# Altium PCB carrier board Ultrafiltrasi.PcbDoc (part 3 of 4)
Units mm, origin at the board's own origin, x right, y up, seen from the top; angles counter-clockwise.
Board outline 216.53 x 247.52 mm, 2 copper layers (Top Layer, Bottom Layer); 114 components, 209 nets, 667 pads, 68 vias.
Unrouted connection lines stored in the file: 3.

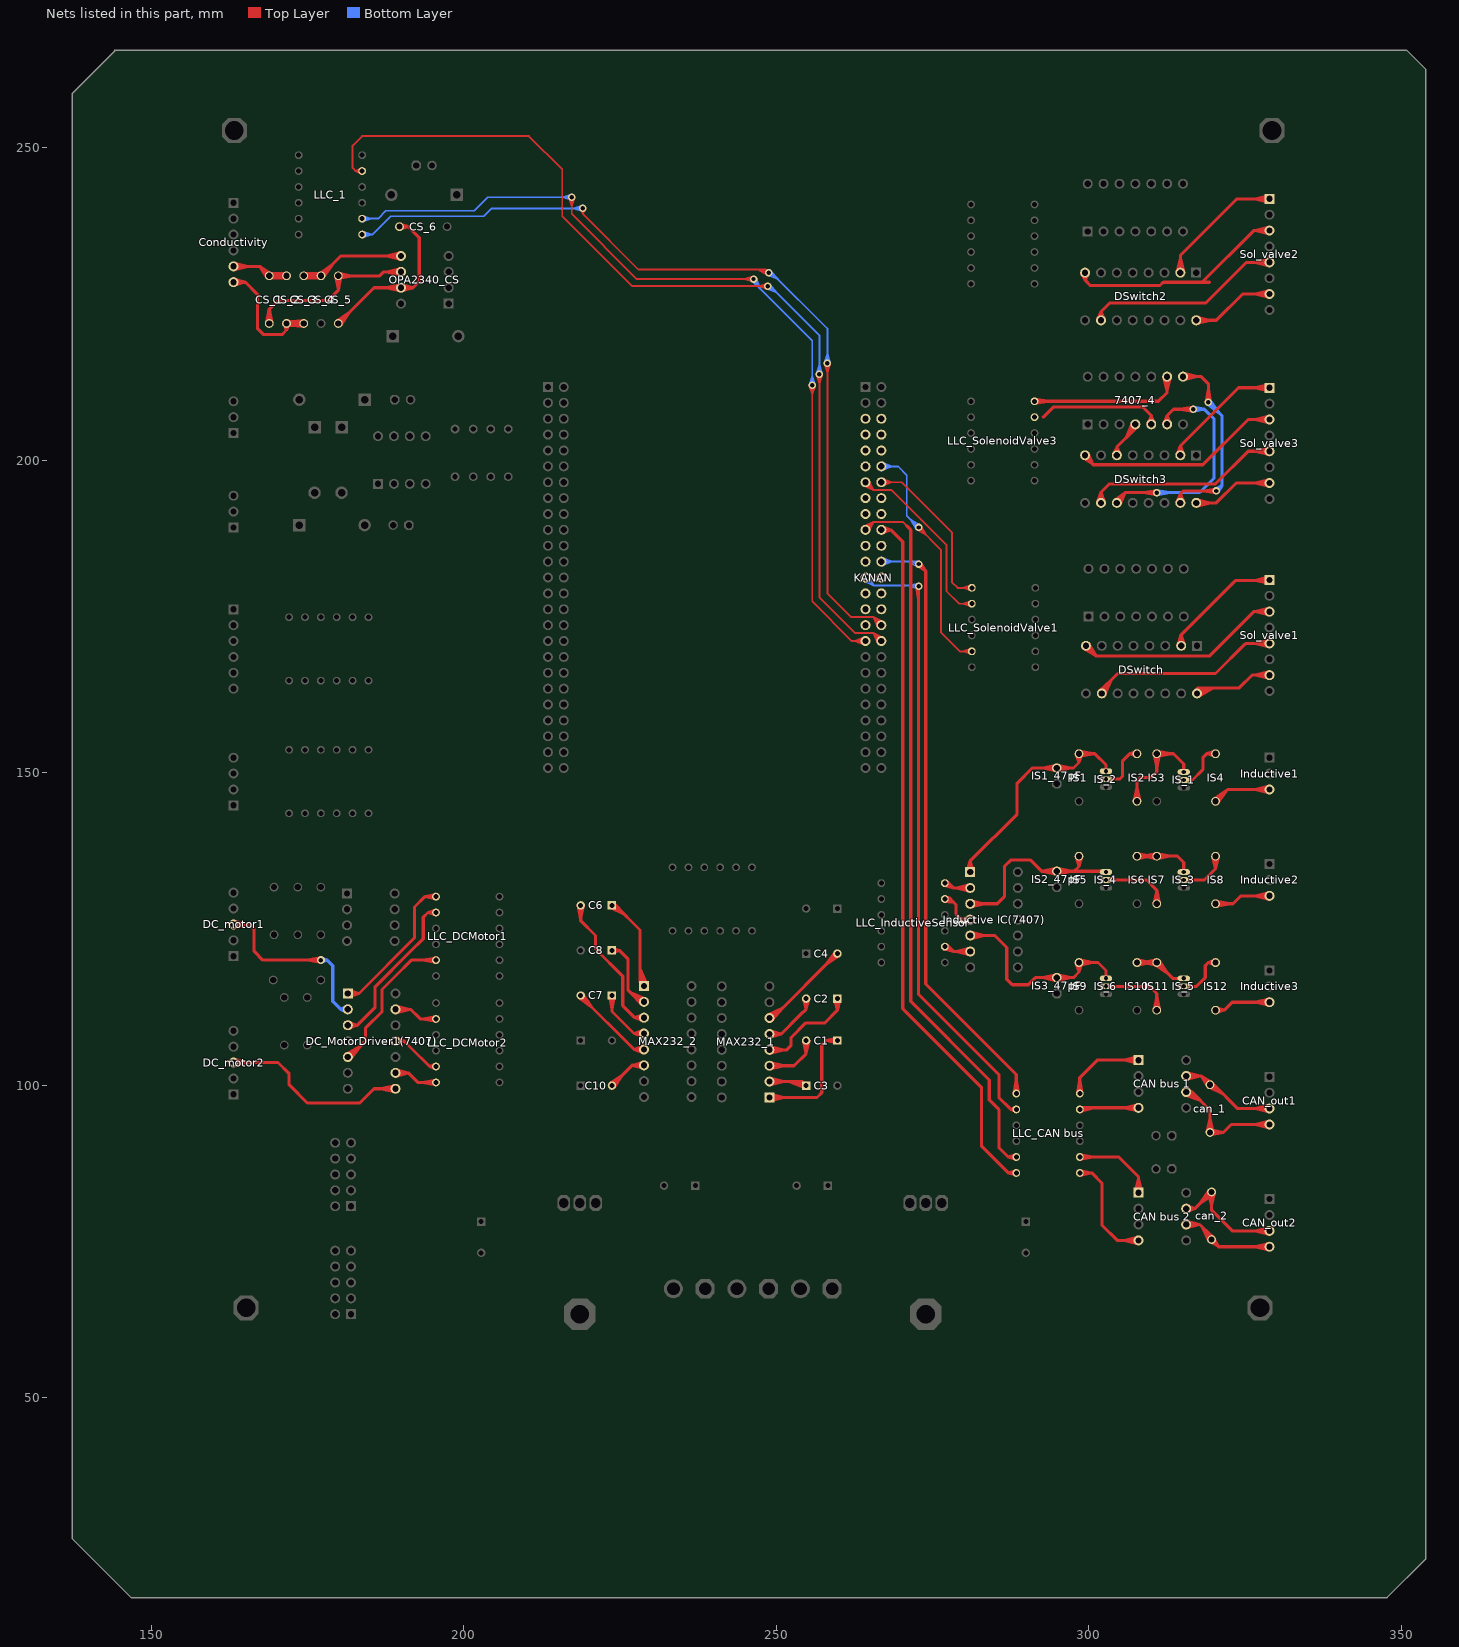
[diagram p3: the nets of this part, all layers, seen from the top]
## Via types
v1: diameter 1.2, hole 0.711, Top Layer to Bottom Layer, 27 vias
v2: diameter 1.27, hole 0.711, Top Layer to Bottom Layer, 21 vias
v3: diameter 1.2, hole 0.7, Top Layer to Bottom Layer, 19 vias
v4: diameter 1.5, hole 0.8, Top Layer to Bottom Layer, 1 vias

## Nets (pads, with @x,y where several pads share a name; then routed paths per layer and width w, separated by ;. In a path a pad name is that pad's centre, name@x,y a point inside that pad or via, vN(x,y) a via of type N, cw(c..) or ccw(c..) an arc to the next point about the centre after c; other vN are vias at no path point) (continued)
Net7407_4_4: 7407_4.4 DSwitch3.6 | length 16.9
  Top Layer w0.5: DSwitch3.6@303.969,200.903 304.507,202.096 ; DSwitch3.6@304.507,200.787 304.507,202.096 ; DSwitch3.6@305.045,200.903 304.507,202.096 ; 7407_4.4@306.985,206.005 305.94,203.529 ; 7407_4.4@307.885,205.383 305.94,203.529 ; 304.507,202.096 307.467,205.056 7407_4.4@307.467,205.74 305.94,203.529
Net7407_4_5: 7407_4.5 LLC_SolenoidValve3.P$11 | length 23.1
  Top Layer w0.5: LLC_SolenoidValve3.P$11@291.338,206.883 LLC_SolenoidValve3.P$11@291.611,207.156 ; 292.735,206.883 294.386,208.534 308.61,208.534 310.007,207.137 ; 7407_4.5@309.468,205.848 310.007,207.137 ; 7407_4.5@310.007,205.74 310.007,207.137 ; 7407_4.5@310.546,205.848 310.007,207.137
Net7407_4_6: 7407_4.6 DSwitch3.11 | length 64.6
  Top Layer w0.5: DSwitch3.11@304.124,193.562 305.816,194.818 ; DSwitch3.11@304.979,192.884 305.816,194.818 ; v3@310.867,194.469 308.796,194.818 v3@310.867,195.167 ; v3@311.162,195.072 311.15,195.072 v3(310.896,194.818) 305.816,194.818 ; 7407_4.6@312.008,205.848 312.547,207.137 ; 7407_4.6@312.547,205.74 312.547,207.137 ; 7407_4.6@313.086,205.848 312.547,207.137 ; v1@316.709,207.804 314.638,208.153 ; v1@316.709,208.502 314.638,208.153 ; 305.816,194.818 DSwitch3.11@304.507,193.167 304.507,193.509 305.816,194.818 ; 312.547,207.137 313.563,208.153 v1(316.738,208.153) 314.638,208.153
  Bottom Layer w0.5: v3(310.896,194.818) 317.754,194.818 320.04,197.104 320.04,206.629 318.516,208.153 ; v3@310.925,194.469 312.996,194.818 v3@310.925,195.167 ; v1(316.738,208.153) 318.516,208.153 ; v1@316.772,207.805 318.516,208.153 ; v1@316.772,208.501 318.516,208.153
Net7407_4_8: 7407_4.8 DSwitch3.15 | length 55.5
  Top Layer w0.5: DSwitch3.15@314.127,193.272 314.667,194.603 ; DSwitch3.15@314.667,193.167 314.667,194.603 ; 7407_4.8@315.087,213.36 318.008,213.36 319.151,212.217 v3(319.151,209.296) ; 7407_4.8@315.153,212.814 317.387,213.36 7407_4.8@315.153,213.906 ; DSwitch3.15@315.207,193.272 314.667,194.603 ; v3@318.802,209.325 319.151,211.396 v3@319.5,209.325 ; v3@320.392,194.723 318.321,195.072 ; v3@320.392,195.421 318.321,195.072 ; 314.667,194.603 315.136,195.072 v3(320.421,195.072) 318.321,195.072
  Bottom Layer w0.5: v3@318.923,209.031 320.812,207.635 v3@319.416,209.524 ; v3(319.151,209.296) 321.31,207.137 321.31,195.961 ; v3@320.21,195.352 321.31,195.961 ; v3(320.421,195.072) 321.31,195.961 ; v3@320.701,194.861 321.31,195.961
Net7407_4_9: 7407_4.9 LLC_SolenoidValve3.P$12 | length 33.2
  Top Layer w0.5: LLC_SolenoidValve3.P$12@291.338,209.423 311.15,209.423 312.547,210.82 7407_4.9@312.547,213.36 ; LLC_SolenoidValve3.P$12@291.371,209.049 293.463,209.423 LLC_SolenoidValve3.P$12@291.371,209.797 ; 7407_4.9@312.001,213.294 312.547,211.06 7407_4.9@313.093,213.294
NetC1_1: C1.1 MAX232_1.1 | length 27.3
  Top Layer w0.5: MAX232_1.1@248.92,98.044 256.54,98.044 257.302,98.806 257.302,106.426 258.032,107.156 ; MAX232_1.1@248.986,97.498 251.22,98.044 MAX232_1.1@248.986,98.59 ; C1.1@259.751,106.734 258.032,107.156 ; C1.1@259.751,107.578 258.032,107.156 ; C1.1@259.802,107.156 258.032,107.156
NetC1_2: C1.2 MAX232_1.3 | length 19.6
  Top Layer w0.5: MAX232_1.3@248.92,103.124 252.857,103.124 254.802,105.069 ; MAX232_1.3@248.986,102.578 251.22,103.124 MAX232_1.3@248.986,103.67 ; C1.2@254.379,107.113 254.802,105.069 ; C1.2@255.225,107.113 254.802,105.069 ; 254.802,105.069 C1.2@254.802,107.156 254.802,105.069
NetC2_1: C2.1 MAX232_1.4 | length 26.6
  Top Layer w0.5: MAX232_1.4@248.92,105.664 251.714,105.664 252.349,106.299 252.349,107.569 254.762,109.982 257.81,109.982 259.802,111.974 ; MAX232_1.4@248.986,105.118 251.22,105.664 MAX232_1.4@248.986,106.21 ; C2.1@259.38,113.807 259.802,111.974 ; C2.1@259.802,113.855 259.802,111.974 ; C2.1@259.802,114.088 259.802,111.974 ; C2.1@260.224,113.807 259.802,111.974
NetC2_2: C2.2 MAX232_1.5 | length 18
  Top Layer w0.5: MAX232_1.5@248.92,108.204 250.825,108.204 ; MAX232_1.5@248.999,107.66 250.825,108.204 ; MAX232_1.5@248.999,108.748 250.825,108.204 ; C2.2@254.38,113.802 254.802,112.181 ; C2.2@255.224,113.802 254.802,112.181 ; 250.825,108.204 253.873,111.252 254.802,112.181 ; 254.802,112.181 C2.2@254.802,113.855 254.802,112.181
NetC3_1: C3.1 MAX232_1.2 | length 19.1
  Top Layer w0.5: MAX232_1.2@248.92,100.584 254.167,100.584 C3.1@254.802,99.949 252.103,100.584 ; MAX232_1.2@248.986,100.038 251.22,100.584 MAX232_1.2@248.986,101.13 ; C3.1@254.673,99.544 252.103,100.584 ; C3.1@254.867,100.369 252.103,100.584
NetC4_2: C4.2 MAX232_1.6 | length 30.6
  Top Layer w0.5: MAX232_1.6@248.633,111.213 251.066,112.382 ; MAX232_1.6@249.297,110.343 251.066,112.382 ; C4.2@259.481,121.341 258.04,119.356 ; C4.2@259.774,121.09 249.428,110.744 MAX232_1.6@248.92,110.744 251.066,112.382 ; C4.2@259.802,121.063 258.04,119.356 ; C4.2@260.07,120.733 258.04,119.356
NetC6_1: C6.1 MAX232_2.1 | length 31.3
  Top Layer w0.5: C6.1@223.513,128.415 225.771,127.289 ; C6.1@224.013,129.099 225.771,127.289 ; MAX232_2.1@228.309,115.821 228.219,118.628 ; MAX232_2.1@229.375,116.068 228.219,118.628 ; 225.771,127.289 C6.1@223.734,128.778 224.282,128.778 228.219,124.841 228.219,116.527 MAX232_2.1@228.854,115.892 228.219,118.628
NetC6_2: C6.2 MAX232_2.3 | length 31.8
  Top Layer w0.5: C6.2@218.311,128.736 218.734,126.603 C6.2@219.157,128.736 ; C6.2@218.734,128.778 218.734,126.325 221.107,123.952 221.107,121.793 225.464,117.436 225.464,112.737 227.389,110.812 ; MAX232_2.3@228.751,110.272 227.389,110.812 ; MAX232_2.3@228.751,111.352 227.389,110.812 ; 227.389,110.812 MAX232_2.3@228.854,110.812 227.389,110.812
NetC7_1: C7.1 MAX232_2.4 | length 20.4
  Top Layer w0.5: C7.1@223.311,114.322 223.734,112.189 ; C7.1@224.157,114.322 223.734,112.189 ; MAX232_2.4@228.759,107.73 227.262,108.272 ; MAX232_2.4@228.759,108.814 227.262,108.272 ; 223.734,112.189 C7.1@223.734,114.364 223.734,111.8 227.262,108.272 ; 227.262,108.272 MAX232_2.4@228.854,108.272 227.262,108.272
NetC7_2: C7.2 MAX232_2.5 | length 24.3
  Top Layer w0.5: C7.2@218.451,114.046 220.415,112.579 ; C7.2@218.63,114.364 227.262,105.732 ; C7.2@218.734,114.364 220.415,112.579 ; C7.2@219.067,114.627 220.415,112.579 ; MAX232_2.5@228.759,105.19 227.262,105.732 ; MAX232_2.5@228.759,106.274 227.262,105.732 ; MAX232_2.5@228.854,105.732 227.262,105.732
NetC8_1: C8.1 MAX232_2.2 | length 21.6
  Top Layer w0.5: C8.1@223.734,121.571 224.885,121.571 ; C8.1@223.812,121.153 224.885,121.571 ; C8.1@223.812,121.988 224.885,121.571 ; MAX232_2.2@228.5,112.931 226.676,114.827 ; MAX232_2.2@229.113,113.837 226.676,114.827 ; 224.885,121.571 226.314,120.142 226.314,115.189 228.151,113.352 MAX232_2.2@228.854,113.352 226.676,114.827
NetC10_2: C10.2 MAX232_2.6 | length 15.1
  Top Layer w0.5: C10.2@223.461,100.274 225.47,101.685 C10.2@224.059,99.676 ; C10.2@223.734,99.949 226.977,103.192 ; MAX232_2.6@228.773,102.648 226.977,103.192 ; MAX232_2.6@228.773,103.736 226.977,103.192 ; MAX232_2.6@228.854,103.192 226.977,103.192
"NetCAN bus 1_1": "CAN bus 1.1" "LLC_CAN bus.P$12" | length 21.9
  Top Layer w0.5: 298.203,98.712 298.577,100.804 298.951,98.712 ; 298.577,98.679 298.577,101.219 301.371,104.013 307.975,104.013 ; 307.909,103.467 305.675,104.013 307.909,104.559
"NetCAN bus 1_4": "CAN bus 1.4" "LLC_CAN bus.P$11" | length 23
  Top Layer w0.5: 298.566,96.514 300.771,96.393 ; 298.652,95.771 300.771,96.393 ; 307.909,95.847 305.675,96.393 ; 307.909,96.939 305.675,96.393 ; 300.771,96.393 298.577,96.139 298.831,96.393 307.975,96.393 305.675,96.393
"NetCAN bus 2_1": "CAN bus 2.1" "LLC_CAN bus.P$8" | length 22.1
  Top Layer w0.5: 298.577,88.519 304.8,88.519 307.975,85.344 307.975,82.804 ; 298.61,88.145 300.702,88.519 298.61,88.893 ; 307.429,82.87 307.975,85.104 308.521,82.87
"NetCAN bus 2_4": "CAN bus 2.4" "LLC_CAN bus.P$7" | length 26.2
  Top Layer w0.5: 298.577,85.979 300.482,85.979 ; 298.614,85.606 300.482,85.979 ; 298.614,86.352 300.482,85.979 ; 307.909,74.638 305.675,75.184 307.909,75.73 ; 307.975,75.184 304.546,75.184 302.133,77.597 302.133,84.328 300.482,85.979
Netcan_1_1: "CAN bus 1.6" can_1.1 CAN_out1.4 | length 44.5
  Top Layer w0.5: 315.357,98.437 317.889,97.528 ; 315.929,99.37 317.889,97.528 ; can_1.1@318.957,92.502 319.405,94.656 can_1.1@319.853,92.502 ; can_1.1@319.452,92.008 321.564,92.456 ; can_1.1@319.452,92.904 321.564,92.456 ; CAN_out1.4@328.864,93.18 326.63,93.726 CAN_out1.4@328.864,94.272 ; CAN_out1.4@328.93,93.726 322.834,93.726 321.564,92.456 ; 315.595,98.933 316.484,98.933 ; 315.595,98.933 317.889,97.528 ; 315.595,98.933 316.484,98.933 ; 316.484,98.933 315.765,98.41 316.484,98.933 ; 316.484,98.933 315.765,99.456 316.484,98.933 ; 316.484,98.933 319.405,96.012 can_1.1@319.405,92.456 321.564,92.456
Netcan_1_2: "CAN bus 1.7" can_1.2 CAN_out1.3 | length 38.4
  Top Layer w0.5: 315.595,101.473 318.008,101.473 ; 315.661,100.927 317.895,101.473 315.661,102.019 ; can_1.2@319.053,99.796 318.008,101.473 ; can_1.2@319.18,99.686 321.527,98.589 ; can_1.2@319.685,100.428 318.008,101.473 ; can_1.2@319.694,100.421 321.527,98.589 ; CAN_out1.3@328.864,95.72 326.63,96.266 CAN_out1.3@328.864,96.812 ; CAN_out1.3@328.93,96.266 323.85,96.266 320.04,100.076 can_1.2@319.405,100.076 ; 318.008,101.473 can_1.2@319.405,100.076 ; 318.008,101.473 can_1.2@319.405,100.076 ; can_1.2@319.405,100.076 321.527,98.589
Netcan_2_1: "CAN bus 2.6" can_2.1 CAN_out2.4 | length 34.7
  Top Layer w0.5: 315.595,77.724 317.754,77.724 ; 315.665,77.178 317.754,77.724 ; 315.665,78.27 317.754,77.724 ; can_2.1@319.275,75.076 318.185,77.293 ; can_2.1@319.388,74.952 320.802,74.168 ; can_2.1@319.994,75.611 318.185,77.293 ; can_2.1@320.018,75.582 320.802,74.168 ; CAN_out2.4@328.864,73.622 326.63,74.168 CAN_out2.4@328.864,74.714 ; CAN_out2.4@328.93,74.168 320.802,74.168 ; 317.754,77.724 319.659,75.819 can_2.1@319.659,75.311 ; 318.185,77.293 can_2.1@319.659,75.311 ; can_2.1@319.659,75.311 320.802,74.168
Netcan_2_2: "CAN bus 2.7" can_2.2 CAN_out2.3 | length 35.5
  Top Layer w0.5: 315.595,80.264 316.992,80.264 ; 315.703,79.725 316.992,80.264 ; 315.703,80.803 316.992,80.264 ; can_2.2@319.211,82.885 319.659,80.731 can_2.2@320.107,82.885 ; can_2.2@319.313,83.219 317.898,81.17 can_2.2@319.947,82.585 ; CAN_out2.3@328.864,76.162 326.63,76.708 CAN_out2.3@328.864,77.254 ; CAN_out2.3@328.93,76.708 322.961,76.708 319.659,80.01 can_2.2@319.659,82.931 316.992,80.264
NetConductivity_5: Conductivity.5 CS_1.1 CS_2.2 | length 40.2
  Top Layer w0.5: Conductivity.5@163.195,231.013 167.386,231.013 ; Conductivity.5@163.261,230.467 165.495,231.013 Conductivity.5@163.261,231.559 ; CS_1.1@168.56,229.206 167.386,231.013 ; CS_1.1@168.956,229.041 171.11,229.489 CS_1.1@168.956,229.937 ; CS_1.1@169.193,229.839 167.386,231.013 ; CS_2.2@171.559,229.054 CS_1.1@169.465,229.831 ; CS_2.2@171.559,229.924 CS_1.1@169.465,229.147 ; CS_2.2@171.626,229.041 169.472,229.489 CS_2.2@171.626,229.937 ; CS_2.2@171.696,229.04 CS_1.1@169.465,229.147 ; CS_2.2@171.696,229.938 CS_1.1@169.465,229.831 ; 167.386,231.013 CS_1.1@168.91,229.489 CS_2.2@171.672,229.489 ; CS_1.1@169.465,229.147 CS_2.2@171.672,229.489 ; CS_1.1@169.465,229.831 CS_2.2@171.672,229.489
NetConductivity_6: Conductivity.6 CS_2.1 CS_3.1 | length 47.4
  Top Layer w0.5: Conductivity.6@163.195,228.473 165.1,228.473 ; Conductivity.6@163.274,227.929 165.1,228.473 ; Conductivity.6@163.274,229.017 165.1,228.473 ; CS_2.1@171.233,221.772 171.672,220.821 ; CS_2.1@171.718,221.421 173.872,221.869 CS_2.1@171.718,222.317 ; CS_2.1@172.112,221.772 171.672,220.821 ; CS_3.1@174.321,221.434 CS_2.1@172.228,222.211 ; CS_3.1@174.321,222.304 CS_2.1@172.228,221.527 ; CS_3.1@174.388,221.421 172.235,221.869 CS_3.1@174.388,222.317 ; CS_3.1@174.458,221.42 CS_2.1@172.228,221.527 ; CS_3.1@174.458,222.318 CS_2.1@172.228,222.211 ; 165.1,228.473 167.005,226.568 167.005,221.107 168.021,220.091 170.942,220.091 171.672,220.821 ; 171.672,220.821 CS_2.1@171.672,221.869 CS_3.1@174.434,221.869 ; CS_2.1@172.228,221.527 CS_3.1@174.434,221.869 ; CS_2.1@172.228,222.211 CS_3.1@174.434,221.869
NetCS_1_2: CS_1.2 CS_5.1 OPA2340_CS.6 | length 47.2
  Top Layer w0.5: CS_1.2@168.462,221.915 168.91,224.069 CS_1.2@169.358,221.915 ; CS_1.2@168.91,221.869 168.91,224.155 170.307,225.552 178.308,225.552 179.959,227.203 CS_5.1@179.959,229.489 ; CS_5.1@179.511,229.443 179.959,227.289 ; CS_5.1@180.005,229.041 182.159,229.489 CS_5.1@180.005,229.937 ; CS_5.1@180.407,229.443 179.959,227.289 ; OPA2340_CS.6@189.926,229.578 187.692,230.124 OPA2340_CS.6@189.926,230.67 ; OPA2340_CS.6@189.992,230.124 187.198,230.124 186.563,229.489 CS_5.1@179.959,229.489 ; 179.959,227.289 CS_5.1@179.959,229.489
NetCS_3_2: CS_3.2 CS_4.2 OPA2340_CS.5 | length 48.7
  Top Layer w0.5: CS_3.2@174.434,229.489 CS_4.2@177.197,229.489 ; CS_3.2@174.481,229.041 176.634,229.489 CS_3.2@174.481,229.937 ; CS_4.2@176.909,229.835 178.957,231.25 CS_4.2@177.542,229.201 ; CS_4.2@177.083,229.054 CS_3.2@174.99,229.831 ; CS_4.2@177.083,229.924 CS_3.2@174.99,229.147 ; CS_4.2@177.151,229.041 174.997,229.489 CS_4.2@177.151,229.937 ; CS_4.2@177.22,229.04 CS_3.2@174.99,229.147 ; CS_4.2@177.22,229.938 CS_3.2@174.99,229.831 ; OPA2340_CS.5@189.926,232.118 187.692,232.664 OPA2340_CS.5@189.926,233.21 ; OPA2340_CS.5@189.992,232.664 180.372,232.664 CS_4.2@177.197,229.489 ; CS_3.2@174.99,229.147 CS_4.2@177.197,229.489 ; CS_3.2@174.99,229.831 CS_4.2@177.197,229.489
NetCS_5_2: CS_5.2 CS_6.1 OPA2340_CS.7 | length 42.8
  Top Layer w0.5: CS_5.2@179.671,222.215 181.72,223.63 CS_5.2@180.305,221.581 ; CS_5.2@179.959,221.869 185.674,227.584 OPA2340_CS.7@189.992,227.584 191.897,227.584 ; CS_6.1@189.738,237.363 191.135,237.363 ; CS_6.1@189.81,236.919 191.135,237.363 ; CS_6.1@189.81,237.807 191.135,237.363 ; OPA2340_CS.7@189.926,227.038 187.692,227.584 OPA2340_CS.7@189.926,228.13 ; OPA2340_CS.7@190.071,227.04 191.897,227.584 ; OPA2340_CS.7@190.071,228.128 191.897,227.584 ; 191.135,237.363 192.913,235.585 192.913,228.6 191.897,227.584
NetDC_motor1_3: DC_motor1.3 DC_MotorDriver1(7407).2 | length 44.7
  Top Layer w0.5: DC_motor1.3@163.195,125.73 165.735,125.73 166.497,124.968 166.497,121.412 167.894,120.015 v2(177.165,120.015) 175.03,120.015 ; DC_motor1.3@163.261,125.184 165.495,125.73 DC_motor1.3@163.261,126.276 ; v2@177.13,119.632 175.03,120.015 ; v2@177.13,120.398 175.03,120.015
  Bottom Layer w0.5: v2(177.165,120.015) 178.181,120.015 ; v2@177.238,119.637 178.181,120.015 ; v2@177.238,120.393 178.181,120.015 ; 181.351,111.607 180.34,112.141 ; 181.351,112.675 180.34,112.141 ; 181.483,112.141 180.34,112.141 ; 178.181,120.015 179.07,119.126 179.07,113.411 180.34,112.141
NetDC_motor2_3: DC_motor2.3 DC_MotorDriver1(7407).8 | length 39.8
  Top Layer w0.5: DC_motor2.3@163.195,103.632 170.307,103.632 172.085,101.854 172.085,100.076 175.006,97.155 183.388,97.155 185.674,99.441 189.103,99.441 ; DC_motor2.3@163.261,103.086 165.495,103.632 DC_motor2.3@163.261,104.178 ; 189.037,98.895 186.803,99.441 189.037,99.987
NetDC_MotorDriver1(7407)_1: DC_MotorDriver1(7407).1 LLC_DCMotor1.P$7 | length 32.3
  Top Layer w0.5: 181.483,114.681 183.261,114.681 ; 181.568,114.138 183.261,114.681 ; 181.568,115.224 183.261,114.681 ; LLC_DCMotor1.P$7@195.54,129.802 193.802,130.175 ; LLC_DCMotor1.P$7@195.54,130.548 193.802,130.175 ; 183.261,114.681 192.151,123.571 192.151,128.524 193.802,130.175 ; 193.802,130.175 LLC_DCMotor1.P$7@195.58,130.175 193.802,130.175
NetDC_MotorDriver1(7407)_3: DC_MotorDriver1(7407).3 LLC_DCMotor1.P$8 | length 32.4
  Top Layer w0.5: 181.483,109.601 183.007,109.601 ; 181.582,109.06 183.007,109.601 ; 181.582,110.142 183.007,109.601 ; LLC_DCMotor1.P$8@195.525,127.264 194.31,127.635 ; LLC_DCMotor1.P$8@195.525,128.006 194.31,127.635 ; 183.007,109.601 185.801,112.395 185.801,115.697 191.516,121.412 193.548,123.444 193.548,126.873 194.31,127.635 ; 194.31,127.635 LLC_DCMotor1.P$8@195.58,127.635 194.31,127.635
NetDC_MotorDriver1(7407)_5: DC_MotorDriver1(7407).5 LLC_DCMotor1.P$11 | length 35.8
  Top Layer w0.5: 181.168,104.972 183.441,106.225 ; 181.886,104.147 183.441,106.225 ; LLC_DCMotor1.P$11@195.547,119.641 193.455,120.015 LLC_DCMotor1.P$11@195.547,120.389 ; LLC_DCMotor1.P$11@195.58,120.015 191.643,120.015 189.103,117.475 186.944,115.316 186.944,111.76 184.277,109.093 184.277,107.061 181.737,104.521 181.483,104.521 183.441,106.225
NetDC_MotorDriver1(7407)_9: DC_MotorDriver1(7407).9 LLC_DCMotor2.P$12 | length 15.4
  Top Layer w0.5: 189.103,101.981 191.135,101.981 ; 189.177,101.436 191.135,101.981 ; 189.177,102.526 191.135,101.981 ; LLC_DCMotor2.P$12@195.547,100.083 193.455,100.457 LLC_DCMotor2.P$12@195.547,100.831 ; LLC_DCMotor2.P$12@195.58,100.457 192.659,100.457 191.135,101.981
NetDC_MotorDriver1(7407)_11: DC_MotorDriver1(7407).11 LLC_DCMotor2.P$11 | length 13
  Top Layer w0.5: 189.103,107.061 190.5,107.061 ; 189.211,106.522 190.5,107.061 ; 189.211,107.6 190.5,107.061 ; LLC_DCMotor2.P$11@195.511,102.628 194.564,102.997 ; LLC_DCMotor2.P$11@195.511,103.366 194.564,102.997 ; LLC_DCMotor2.P$11@195.58,102.997 194.564,102.997 ; 190.5,107.061 191.516,106.045 194.564,102.997
NetDC_MotorDriver1(7407)_13: DC_MotorDriver1(7407).13 LLC_DCMotor2.P$8 | length 16
  Top Layer w0.5: 189.103,112.141 191.516,112.141 193.04,110.617 LLC_DCMotor2.P$8@195.58,110.617 ; 189.169,111.595 191.403,112.141 189.169,112.687 ; LLC_DCMotor2.P$8@195.547,110.243 193.455,110.617 LLC_DCMotor2.P$8@195.547,110.991
NetDSwitch2_2: DSwitch2.2 Sol_valve2.1 | length 32.1
  Top Layer w0.5: DSwitch2.2@314.121,230.063 314.667,232.297 DSwitch2.2@315.213,230.063 ; DSwitch2.2@314.667,229.997 314.667,232.752 323.723,241.808 Sol_valve2.1@328.803,241.808 ; Sol_valve2.1@328.864,241.262 326.63,241.808 ; Sol_valve2.1@328.864,242.354 326.63,241.808 ; Sol_valve2.1@328.93,241.808 326.63,241.808
NetDSwitch2_8: DSwitch2.8 Sol_valve2.3 | length 45.1
  Top Layer w0.5: DSwitch2.8@298.891,229.874 299.427,228.766 ; DSwitch2.8@299.427,229.997 299.427,228.766 ; DSwitch2.8@299.963,229.874 299.427,228.766 ; 318.135,228.473 326.39,236.728 Sol_valve2.3@328.803,236.728 ; 319.278,228.473 311.942,228.473 311.419,227.95 300.243,227.95 299.427,228.766 ; Sol_valve2.3@328.864,236.182 326.63,236.728 ; Sol_valve2.3@328.864,237.274 326.63,236.728 ; Sol_valve2.3@328.93,236.728 326.63,236.728
NetDSwitch2_10: DSwitch2.10 Sol_valve2.5 | length 41
  Top Layer w0.5: DSwitch2.10@301.428,222.488 301.967,223.735 ; DSwitch2.10@301.967,222.377 301.967,223.735 ; DSwitch2.10@302.506,222.488 301.967,223.735 ; Sol_valve2.5@328.676,231.648 325.247,231.648 318.77,225.171 303.403,225.171 301.967,223.735 ; Sol_valve2.5@328.864,231.102 326.63,231.648 ; Sol_valve2.5@328.864,232.194 326.63,231.648 ; Sol_valve2.5@328.93,231.648 326.63,231.648
NetDSwitch2_16: DSwitch2.16 Sol_valve2.7 | length 22.7
  Top Layer w0.5: DSwitch2.16@317.207,222.377 320.421,222.377 324.612,226.568 Sol_valve2.7@328.93,226.568 ; DSwitch2.16@317.273,221.831 319.507,222.377 DSwitch2.16@317.273,222.923 ; Sol_valve2.7@328.864,226.022 326.63,226.568 Sol_valve2.7@328.864,227.114
NetDSwitch3_2: DSwitch3.2 Sol_valve3.1 | length 29.2
  Top Layer w0.5: DSwitch3.2@314.127,200.889 314.667,202.272 ; DSwitch3.2@314.667,200.787 314.667,202.272 ; DSwitch3.2@315.208,200.889 314.667,202.272 ; 323.977,211.582 314.667,202.272 ; 324.104,211.582 Sol_valve3.1@328.803,211.582 ; Sol_valve3.1@328.864,211.036 326.63,211.582 ; Sol_valve3.1@328.864,212.128 326.63,211.582 ; Sol_valve3.1@328.93,211.582 326.63,211.582
NetDSwitch3_8: DSwitch3.8 Sol_valve3.3 | length 45.9
  Top Layer w0.5: DSwitch3.8@299.063,200.375 300.736,199.263 ; DSwitch3.8@299.889,201.085 300.736,199.263 ; Sol_valve3.3@328.676,206.502 325.501,206.502 318.262,199.263 300.736,199.263 ; Sol_valve3.3@328.864,205.956 326.63,206.502 ; Sol_valve3.3@328.864,207.048 326.63,206.502 ; Sol_valve3.3@328.93,206.502 326.63,206.502 ; 300.736,199.263 DSwitch3.8@299.427,200.787 299.427,200.572 300.736,199.263
NetDSwitch3_10: DSwitch3.10 Sol_valve3.5 | length 41.4
  Top Layer w0.5: DSwitch3.10@301.424,193.256 301.967,194.857 ; DSwitch3.10@301.967,193.167 301.967,194.857 ; DSwitch3.10@302.51,193.256 301.967,194.857 ; Sol_valve3.5@328.676,201.422 325.501,201.422 320.294,196.215 303.325,196.215 301.967,194.857 ; Sol_valve3.5@328.864,200.876 326.63,201.422 ; Sol_valve3.5@328.864,201.968 326.63,201.422 ; Sol_valve3.5@328.93,201.422 326.63,201.422
NetDSwitch3_16: DSwitch3.16 Sol_valve3.7 | length 24.3
  Top Layer w0.5: DSwitch3.16@317.207,193.167 320.421,193.167 323.596,196.342 Sol_valve3.7@328.676,196.342 ; DSwitch3.16@317.273,192.621 319.507,193.167 DSwitch3.16@317.273,193.713 ; Sol_valve3.7@328.864,195.796 326.63,196.342 ; Sol_valve3.7@328.864,196.888 326.63,196.342 ; Sol_valve3.7@328.93,196.342 326.63,196.342
NetDSwitch_2: DSwitch.2 Sol_valve1.1 | length 29.9
  Top Layer w0.5: DSwitch.2@314.251,170.394 314.794,172.046 ; DSwitch.2@314.794,170.307 314.794,172.046 ; DSwitch.2@315.337,170.394 314.794,172.046 ; Sol_valve1.1@328.835,181.39 326.623,180.721 ; Sol_valve1.1@328.895,180.299 326.623,180.721 ; Sol_valve1.1@328.93,180.721 323.469,180.721 314.794,172.046 ; Sol_valve1.1@328.93,180.848 326.623,180.721
NetDSwitch_8: DSwitch.8 Sol_valve1.3 | length 42.3
  Top Layer w0.5: DSwitch.8@299.214,169.875 301.205,168.656 ; DSwitch.8@299.554,170.307 301.205,168.656 ; DSwitch.8@299.986,170.647 301.205,168.656 ; Sol_valve1.3@328.864,175.222 326.63,175.768 Sol_valve1.3@328.864,176.314 ; Sol_valve1.3@328.93,175.768 326.39,175.768 319.278,168.656 301.205,168.656
NetDSwitch_10: DSwitch.10 Sol_valve1.5 | length 50.7
  Top Layer w0.5: DSwitch.10@301.684,163.053 303.615,164.804 ; DSwitch.10@302.572,162.415 303.615,164.804 ; 324.993,170.561 320.294,165.862 304.673,165.862 302.387,163.576 ; 325.12,170.688 Sol_valve1.5@328.93,170.688 326.63,170.688 ; Sol_valve1.5@328.864,170.142 326.63,170.688 ; Sol_valve1.5@328.864,171.234 326.63,170.688 ; DSwitch.10@302.094,162.687 302.387,163.576 ; DSwitch.10@302.094,162.687 303.615,164.804 ; DSwitch.10@302.094,162.687 302.387,163.576 ; DSwitch.10@302.094,162.687 302.387,162.98 302.387,163.576 ; 302.387,163.576 302.644,162.676 302.387,163.576 ; 302.387,163.576 301.645,163.005 302.387,163.576
NetDSwitch_16: DSwitch.16 Sol_valve1.7 | length 32.6
  Top Layer w0.5: DSwitch.16@317.21,163.223 319.954,163.576 ; DSwitch.16@317.562,162.186 319.954,163.576 ; Sol_valve1.7@328.781,165.079 327.914,165.608 ; Sol_valve1.7@328.781,166.137 327.914,165.608 ; Sol_valve1.7@328.864,165.062 326.63,165.608 Sol_valve1.7@328.864,166.154 ; DSwitch.16@317.334,162.687 317.5,163.576 ; DSwitch.16@317.334,162.687 319.954,163.576 ; DSwitch.16@317.334,162.687 317.5,163.576 ; DSwitch.16@317.334,162.687 317.334,163.41 317.5,163.576 ; 317.5,163.576 317.88,162.755 317.5,163.576 ; 317.5,163.576 316.85,162.948 317.5,163.576 ; 317.5,163.576 324.104,163.576 326.136,165.608 327.914,165.608
NetInductive1_3: Inductive1.3 IS4.2 | length 19
  Top Layer w0.5: IS4.2@320.006,145.761 322.055,147.176 IS4.2@320.64,145.127 ; IS4.2@320.294,145.415 322.199,147.32 Inductive1.3@328.93,147.32 ; Inductive1.3@328.864,146.774 326.63,147.32 Inductive1.3@328.864,147.866
NetInductive2_3: Inductive2.3 IS8.2 | length 18.2
  Top Layer w0.5: IS8.2@320.294,129.032 323.088,129.032 324.358,130.302 Inductive2.3@328.93,130.302 ; IS8.2@320.34,128.584 322.494,129.032 IS8.2@320.34,129.48 ; Inductive2.3@328.864,129.756 326.63,130.302 Inductive2.3@328.864,130.848
NetInductive3_3: Inductive3.3 IS12.2 | length 16.6
  Top Layer w0.5: IS12.2@320.294,112.014 321.691,112.014 ; IS12.2@320.366,111.57 321.691,112.014 ; IS12.2@320.366,112.458 321.691,112.014 ; Inductive3.3@328.864,112.738 326.63,113.284 Inductive3.3@328.864,113.83 ; Inductive3.3@328.93,113.284 322.961,113.284 321.691,112.014
"NetInductive IC(7407)_1": "Inductive IC(7407).1" IS1.2 IS1_47pF.2 IS_2.1 | length 55.9
  Top Layer w0.5: 280.508,134.197 281.051,135.89 ; 281.051,134.112 281.051,135.89 ; 281.594,134.197 281.051,135.89 ; IS1_47pF.2@294.836,150.24 292.632,150.749 IS1_47pF.2@294.836,151.258 ; IS1_47pF.2@294.952,150.24 297.156,150.749 IS1_47pF.2@294.952,151.258 ; IS1.2@298.006,152.963 298.45,151.638 ; IS1.2@298.496,152.587 300.65,153.035 IS1.2@298.496,153.483 ; IS1.2@298.894,152.963 298.45,151.638 ; IS_2.1@302.768,150.241 302.768,151.257 300.99,153.035 IS1.2@298.45,153.035 298.45,151.638 ; 281.051,135.89 288.544,143.383 288.544,148.336 290.957,150.749 IS1_47pF.2@294.894,150.749 297.561,150.749 298.45,151.638
"NetInductive IC(7407)_2": "Inductive IC(7407).2" LLC_InductiveSensor.P$12 | length 13.8
  Top Layer w0.5: LLC_InductiveSensor.P$12@276.847,131.986 278.384,131.572 ; LLC_InductiveSensor.P$12@276.987,132.334 278.384,131.572 ; LLC_InductiveSensor.P$12@276.987,132.461 277.495,132.461 278.384,131.572 ; LLC_InductiveSensor.P$12@277.204,132.64 278.384,131.572 ; 280.985,131.026 278.751,131.572 280.985,132.118 ; 281.051,131.572 278.384,131.572
"NetInductive IC(7407)_3": "Inductive IC(7407).3" IS2_47pF.2 IS5.2 IS_4.1 | length 52.2
  Top Layer w0.5: 281.051,129.032 285.369,129.032 286.512,130.175 286.512,135.001 287.528,136.017 290.703,136.017 292.481,134.239 IS2_47pF.2@294.894,134.239 ; 281.117,128.486 283.351,129.032 281.117,129.578 ; IS2_47pF.2@294.836,133.73 292.632,134.239 ; IS2_47pF.2@294.836,134.748 292.632,134.239 ; IS2_47pF.2@294.952,133.73 297.156,134.239 IS2_47pF.2@294.952,134.748 ; IS5.2@298.004,136.591 298.45,135.001 ; IS5.2@298.45,136.652 298.45,135.001 ; IS5.2@298.896,136.591 298.45,135.001 ; 300.262,134.239 IS_4.1@302.268,134.112 ; IS_4.1@302.768,134.112 302.641,134.239 297.688,134.239 ; 292.632,134.239 IS2_47pF.2@294.894,134.239 ; IS2_47pF.2@294.894,134.239 297.688,134.239 ; 297.688,134.239 298.45,135.001
"NetInductive IC(7407)_4": "Inductive IC(7407).4" LLC_InductiveSensor.P$11 | length 18.3
  Top Layer w0.5: LLC_InductiveSensor.P$11@276.904,129.428 278.384,129.286 ; LLC_InductiveSensor.P$11@276.987,129.921 277.749,129.921 ; LLC_InductiveSensor.P$11@277.159,130.127 278.384,129.286 ; 280.943,125.953 279.654,126.492 ; 280.943,127.031 279.654,126.492 ; 281.051,126.492 279.654,126.492 ; LLC_InductiveSensor.P$11@276.987,129.794 277.749,129.921 ; LLC_InductiveSensor.P$11@276.987,129.794 278.384,129.286 ; LLC_InductiveSensor.P$11@276.987,129.794 277.749,129.921 ; 277.749,129.921 277.137,129.45 277.749,129.921 ; 277.749,129.921 277.017,130.168 277.749,129.921 ; 277.749,129.921 278.384,129.286 ; 278.384,129.286 278.765,128.905 278.765,127.381 279.654,126.492
"NetInductive IC(7407)_5": "Inductive IC(7407).5" IS3_47pF.2 IS9.2 IS_6.1 | length 55.5
  Top Layer w0.5: 281.051,123.952 284.988,123.952 286.893,122.047 286.893,116.967 287.782,116.078 290.322,116.078 291.465,117.221 IS3_47pF.2@294.894,117.221 ; 281.117,123.406 283.351,123.952 281.117,124.498 ; IS3_47pF.2@294.836,116.712 292.632,117.221 ; IS3_47pF.2@294.836,117.73 292.632,117.221 ; IS3_47pF.2@294.952,116.712 297.156,117.221 IS3_47pF.2@294.952,117.73 ; IS9.2@298.005,119.568 298.45,118.11 ; IS9.2@298.496,119.186 300.65,119.634 IS9.2@298.496,120.082 ; IS9.2@298.895,119.568 298.45,118.11 ; IS_6.1@302.768,117.094 302.768,118.364 301.498,119.634 IS9.2@298.45,119.634 298.45,118.11 ; 292.632,117.221 IS3_47pF.2@294.894,117.221 ; IS3_47pF.2@294.894,117.221 297.561,117.221 298.45,118.11
"NetInductive IC(7407)_6": "Inductive IC(7407).6" LLC_InductiveSensor.P$8 | length 13.8
  Top Layer w0.5: LLC_InductiveSensor.P$8@276.847,121.826 278.384,121.412 ; LLC_InductiveSensor.P$8@276.987,122.174 278.384,121.412 ; LLC_InductiveSensor.P$8@276.987,122.301 277.495,122.301 278.384,121.412 ; LLC_InductiveSensor.P$8@277.204,122.48 278.384,121.412 ; 280.985,120.866 278.751,121.412 280.985,121.958 ; 281.051,121.412 278.384,121.412
NetIS2_1: IS2.1 IS_2.2 | length 12
  Top Layer w0.5: IS_2.2@302.768,148.971 304.927,148.971 ; IS_2.2@303.268,148.971 304.927,148.971 ; IS2.1@307.632,152.594 306.578,153.035 ; IS2.1@307.632,153.476 306.578,153.035 ; IS2.1@307.721,153.035 306.578,153.035 ; 304.927,148.971 305.435,149.479 305.435,151.892 306.578,153.035
NetIS2_2: IS2.2 IS3.2 IS_1.1 | length 29.4
  Top Layer w0.5: IS2.2@307.273,145.461 307.721,147.615 IS2.2@308.169,145.461 ; IS2.2@307.721,145.415 307.721,148.717 308.229,149.225 310.007,149.225 310.896,150.114 IS3.2@310.896,153.035 313.563,153.035 315.214,151.384 IS_1.1@315.214,150.114 ; IS3.2@310.448,152.989 310.896,150.835 IS3.2@311.344,152.989 ; IS3.2@310.942,152.587 313.096,153.035 IS3.2@310.942,153.483
NetIS4_1: IS4.1 IS_1.2 | length 13
  Top Layer w0.5: IS_1.2@315.214,148.844 316.611,148.844 ; IS_1.2@315.714,148.844 316.611,148.844 ; IS4.1@320.222,152.591 318.897,153.035 ; IS4.1@320.222,153.479 318.897,153.035 ; 316.611,148.844 318.262,150.495 318.262,152.4 318.897,153.035 ; 318.897,153.035 IS4.1@320.294,153.035 318.897,153.035
NetIS6_2: IS6.2 IS7.2 IS_3.1 | length 22.6
  Top Layer w0.5: IS6.2@307.721,136.652 IS7.2@310.896,136.652 314.198,136.652 315.214,135.636 IS_3.1@315.214,134.112 ; IS6.2@307.767,136.204 309.921,136.652 IS6.2@307.767,137.1 ; IS7.2@310.85,136.204 308.696,136.652 IS7.2@310.85,137.1 ; IS7.2@310.942,136.204 313.096,136.652 IS7.2@310.942,137.1
NetIS7_1: IS7.1 IS_4.2 | length 17.3
  Top Layer w0.5: IS_4.2@302.768,132.842 309.245,132.842 310.896,131.191 ; IS_4.2@303.268,132.842 305.268,132.842 ; IS7.1@310.448,129.079 310.896,131.191 ; IS7.1@310.896,129.032 310.896,131.191 ; IS7.1@311.344,129.079 310.896,131.191
NetIS8_1: IS8.1 IS_3.2 | length 15.9
  Top Layer w0.5: IS_3.2@315.214,132.842 318.516,132.842 320.294,134.62 ; IS_3.2@315.714,132.842 317.714,132.842 ; IS8.1@319.847,136.602 320.294,134.62 ; IS8.1@320.741,136.602 320.294,134.62 ; 320.294,134.62 IS8.1@320.294,136.652 320.294,134.62
NetIS10_2: IS10.2 IS11.2 IS_5.1 | length 23.6
  Top Layer w0.5: IS10.2@307.721,119.634 IS11.2@310.896,119.634 313.436,117.094 ; IS10.2@307.767,119.186 309.921,119.634 IS10.2@307.767,120.082 ; IS11.2@310.608,119.288 312.657,117.873 IS11.2@311.242,119.922 ; IS11.2@310.85,119.186 308.696,119.634 IS11.2@310.85,120.082 ; IS_5.1@314.714,117.094 313.436,117.094 ; IS_5.1@315.214,117.094 313.436,117.094
NetIS11_1: IS11.1 IS_6.2 | length 17.7
  Top Layer w0.5: IS_6.2@302.768,115.824 309.753,115.824 310.896,114.681 IS11.1@310.896,112.014 ; IS_6.2@303.268,115.824 305.268,115.824 ; IS11.1@310.448,112.06 310.896,114.214 IS11.1@311.344,112.06
NetIS12_1: IS12.1 IS_5.2 | length 11.6
  Top Layer w0.5: IS_5.2@315.214,115.824 317.246,115.824 ; IS_5.2@315.714,115.824 317.246,115.824 ; IS12.1@320.205,119.193 319.151,119.634 ; IS12.1@320.205,120.075 319.151,119.634 ; IS12.1@320.294,119.634 319.151,119.634 ; 317.246,115.824 318.643,117.221 318.643,119.126 319.151,119.634
NetKANAN_5: KANAN.5 KANAN.6
NetKANAN_7: KANAN.7
NetKANAN_8: KANAN.8
NetKANAN_9: KANAN.9
NetKANAN_10: KANAN.10
NetKANAN_11: KANAN.11
NetKANAN_12: KANAN.12 LLC_SolenoidValve1.P$5 | length 58.2
  Top Layer w0.3: v1@272.521,188.874 274.032,187.994 v1@273.152,189.505 ; v1(272.796,189.23) 276.352,185.674 276.352,172.466 279.4,169.418 LLC_SolenoidValve1.P$5@281.305,169.418 ; LLC_SolenoidValve1.P$5@281.231,168.949 279.78,169.418 ; LLC_SolenoidValve1.P$5@281.231,169.887 279.78,169.418 ; LLC_SolenoidValve1.P$5@281.295,169.243 279.78,169.418 ; LLC_SolenoidValve1.P$5@281.295,169.593 279.78,169.418
  Bottom Layer w0.3: KANAN.12@266.827,199.009 269.494,199.009 270.891,197.612 270.891,191.135 v1(272.796,189.23) ; KANAN.12@266.863,198.661 268.527,199.009 ; KANAN.12@266.863,199.357 268.527,199.009 ; KANAN.12@266.951,198.371 268.527,199.009 ; KANAN.12@266.951,199.647 268.527,199.009 ; v1@272.44,188.955 271.56,190.466 v1@273.071,189.586
NetKANAN_13: KANAN.13 LLC_SolenoidValve1.P$2 | length 42.7
  Top Layer w0.3: KANAN.13@263.918,195.934 265.557,195.199 ; KANAN.13@264.065,196.199 265.557,195.199 ; KANAN.13@264.287,196.469 265.557,195.199 ; KANAN.13@264.557,196.691 265.557,195.199 ; KANAN.13@264.822,196.838 265.557,195.199 ; LLC_SolenoidValve1.P$2@281.231,176.569 279.78,177.038 ; LLC_SolenoidValve1.P$2@281.231,177.507 279.78,177.038 ; LLC_SolenoidValve1.P$2@281.295,176.863 279.78,177.038 ; LLC_SolenoidValve1.P$2@281.295,177.213 279.78,177.038 ; LLC_SolenoidValve1.P$2@281.305,177.038 279.273,177.038 277.241,179.07 277.241,186.436 268.478,195.199 265.557,195.199
NetKANAN_14: KANAN.14 LLC_SolenoidValve1.P$1 | length 40.6
  Top Layer w0.3: KANAN.14@266.827,196.469 270.129,196.469 278.13,188.468 278.13,180.467 279.019,179.578 LLC_SolenoidValve1.P$1@281.305,179.578 279.78,179.578 ; KANAN.14@266.863,196.121 268.527,196.469 ; KANAN.14@266.863,196.817 268.527,196.469 ; KANAN.14@266.951,195.831 268.527,196.469 ; KANAN.14@266.951,197.107 268.527,196.469 ; LLC_SolenoidValve1.P$1@281.231,179.109 279.78,179.578 ; LLC_SolenoidValve1.P$1@281.231,180.047 279.78,179.578 ; LLC_SolenoidValve1.P$1@281.295,179.403 279.78,179.578 ; LLC_SolenoidValve1.P$1@281.295,179.753 279.78,179.578
NetKANAN_15: KANAN.15
NetKANAN_16: KANAN.16
NetKANAN_17: KANAN.17
NetKANAN_18: KANAN.18
NetKANAN_19: "LLC_CAN bus.P$5" KANAN.19 | length 127.4
  Top Layer w0.3: KANAN.19@263.918,189.384 265.557,190.119 ; KANAN.19@264.065,189.119 265.557,190.119 ; KANAN.19@264.287,188.849 265.557,190.119 ; KANAN.19@264.557,188.627 265.557,190.119 ; KANAN.19@264.822,188.48 265.557,190.119 ; 270.891,189.484 270.256,190.119 265.557,190.119
  Top Layer w0.5: 270.891,189.484 271.526,188.849 271.526,113.411 284.099,100.838 284.099,97.663 285.623,96.139 285.623,90.043 287.147,88.519 ; 288.362,88.148 287.147,88.519 ; 288.362,88.89 287.147,88.519 ; 287.147,88.519 288.417,88.519 287.147,88.519
NetKANAN_20: "LLC_CAN bus.P$6" KANAN.20 | length 119
  Top Layer w0.5: KANAN.20@266.827,188.849 268.351,188.849 ; KANAN.20@266.926,188.308 268.351,188.849 ; KANAN.20@266.926,189.39 268.351,188.849 ; 288.362,85.608 287.147,85.979 ; 288.362,86.35 287.147,85.979 ; 288.417,85.979 287.147,85.979 ; 268.351,188.849 270.256,186.944 270.256,112.268 282.829,99.695 282.829,90.297 287.147,85.979
NetKANAN_21: KANAN.21
NetKANAN_22: KANAN.22
NetKANAN_23: KANAN.23
NetKANAN_24: "LLC_CAN bus.P$1" KANAN.24 | length 116.8
  Top Layer w0.5: v1@272.577,183.115 273.939,182.245 ; v1(272.796,183.388) 273.939,182.245 ; v1@273.069,183.607 273.939,182.245 ; 288.043,98.712 288.417,100.804 288.791,98.712 ; 288.417,98.679 288.417,101.727 273.939,116.205 273.939,138.684 273.939,182.245
  Bottom Layer w0.3: KANAN.24@266.827,183.769 272.415,183.769 v1(272.796,183.388) 271.108,183.769 ; KANAN.24@266.863,183.421 268.527,183.769 ; KANAN.24@266.863,184.117 268.527,183.769 ; KANAN.24@266.951,183.131 268.527,183.769 ; KANAN.24@266.951,184.407 268.527,183.769 ; v1@272.641,182.966 271.108,183.769 ; v1@272.837,183.836 271.108,183.769
NetKANAN_25: "LLC_CAN bus.P$2" KANAN.25 | length 118.4
  Top Layer w0.5: v1@272.447,179.809 272.757,177.731 v1(272.796,179.832) 272.757,179.793 272.757,114.593 285.623,101.727 285.623,98.044 287.528,96.139 ; 288.338,95.772 287.528,96.139 ; 288.338,96.506 287.528,96.139 ; 287.528,96.139 288.417,96.139 287.528,96.139
  Bottom Layer w0.3: KANAN.25@263.918,180.694 265.557,179.959 ; KANAN.25@264.065,180.959 265.557,179.959 ; KANAN.25@264.287,181.229 265.557,179.959 ; KANAN.25@264.557,181.451 265.557,179.959 ; KANAN.25@264.822,181.598 265.557,179.959 ; v1@272.692,179.394 271.282,179.959 ; v1@272.767,180.281 271.282,179.959 ; 265.557,179.959 272.669,179.959 v1(272.796,179.832) 271.282,179.959
NetKANAN_26: KANAN.26
NetKANAN_27: KANAN.27
NetKANAN_28: KANAN.28
NetKANAN_29: KANAN.29
NetKANAN_30: KANAN.30
NetKANAN_31: KANAN.31
NetKANAN_32: KANAN.32 LLC_1.P$1 | length 176.8
  Top Layer w0.3: v1@218.64,240.17 219.075,239.395 ; v1@219.51,240.17 219.075,239.395 ; v1@248.608,229.587 247.116,230.505 ; v1@248.867,230.441 247.116,230.505 ; v1@257.746,215.451 258.191,214.019 ; v1@258.636,215.451 258.191,214.019 ; KANAN.32@266.293,173.239 265.537,174.899 ; KANAN.32@266.557,173.386 265.537,174.899 ; KANAN.32@267.05,173.879 265.537,174.899 ; KANAN.32@267.197,174.143 265.537,174.899 ; 219.075,239.395 v1(219.075,240.284) 219.075,239.395 ; 219.075,239.395 227.965,230.505 248.285,230.505 v1(248.793,229.997) 247.116,230.505 ; 258.191,214.019 v1(258.191,215.519) 258.191,178.689 261.981,174.899 265.537,174.899 ; 265.537,174.899 KANAN.32@266.827,173.609 265.537,174.899
  Bottom Layer w0.3: LLC_1.P$1@183.769,236.093 185.42,236.093 188.341,239.014 203.2,239.014 204.47,240.284 v1(219.075,240.284) ; LLC_1.P$1@183.779,235.918 185.294,236.093 ; LLC_1.P$1@183.779,236.268 185.294,236.093 ; LLC_1.P$1@183.843,235.624 185.294,236.093 ; LLC_1.P$1@183.843,236.562 185.294,236.093 ; v1@219.007,239.839 217.575,240.284 v1@219.007,240.729 ; v1@248.585,229.598 250.299,228.958 ; v1(248.793,229.997) 250.299,228.958 ; v1@248.955,230.089 249.169,230.089 258.191,221.067 v1(258.191,215.519) ; v1@249.092,230.333 250.299,228.958 ; v1@257.746,215.587 258.191,217.019 v1@258.636,215.587
NetKANAN_33: KANAN.33 LLC_1.P$2 | length 175.8
  Top Layer w0.3: v1@216.852,241.994 217.297,240.562 v1@217.742,241.994 ; v1(217.297,242.062) 217.297,239.395 227.711,228.981 v1(246.38,228.981) 244.88,228.981 ; v1@246.312,228.536 244.88,228.981 ; v1@246.312,229.426 244.88,228.981 ; v1@255.333,211.895 255.778,210.463 ; v1@256.223,211.895 255.778,210.463 ; KANAN.33@264.163,170.431 262.587,171.069 ; KANAN.33@264.163,171.707 262.587,171.069 ; KANAN.33@264.251,170.721 262.587,171.069 ; KANAN.33@264.251,171.417 262.587,171.069 ; 255.778,210.463 v1(255.778,211.963) 255.778,177.419 262.128,171.069 KANAN.33@264.287,171.069 262.587,171.069
  Bottom Layer w0.3: LLC_1.P$2@183.769,238.633 186.309,238.633 187.579,239.903 201.676,239.903 203.835,242.062 v1(217.297,242.062) ; LLC_1.P$2@183.779,238.458 185.294,238.633 ; LLC_1.P$2@183.779,238.808 185.294,238.633 ; LLC_1.P$2@183.843,238.164 185.294,238.633 ; LLC_1.P$2@183.843,239.102 185.294,238.633 ; v1@217.229,241.617 215.797,242.062 v1@217.229,242.507 ; v1@246.04,228.687 247.424,227.429 ; v1@246.781,229.185 247.424,227.429 ; v1@255.333,212.031 255.778,213.463 v1@256.223,212.031 ; v1(255.778,211.963) 255.778,219.075 246.38,228.473 v1(246.38,228.981) 247.424,227.429
NetKANAN_34: KANAN.34 LLC_1.P$5 | length 184.3
  Top Layer w0.3: LLC_1.P$5@183.658,245.791 182.753,246.253 ; LLC_1.P$5@183.658,246.715 182.753,246.253 ; LLC_1.P$5@183.754,246.079 182.753,246.253 ; LLC_1.P$5@183.754,246.427 182.753,246.253 ; LLC_1.P$5@183.769,246.253 182.753,246.253 ; v1@248.598,227.393 247.166,227.838 ; v1@248.598,228.283 247.166,227.838 ; v1(248.666,227.838) 247.166,227.838 ; v1@248.92,227.838 226.949,227.838 215.773,239.014 215.773,246.507 210.439,251.841 183.769,251.841 182.245,250.317 182.245,246.761 182.753,246.253 ; v1@256.476,213.673 256.921,212.241 ; v1@257.175,213.487 v1(256.921,213.741) ; v1@257.366,213.673 256.921,212.241 ; KANAN.34@266.292,170.7 265.557,172.339 ; KANAN.34@266.557,170.847 265.557,172.339 ; KANAN.34@267.049,171.339 265.557,172.339 ; KANAN.34@267.196,171.604 265.557,172.339 ; 256.921,212.241 v1(256.921,213.741) ; v1(256.921,213.741) 256.921,178.054 262.636,172.339 265.557,172.339 ; 265.557,172.339 KANAN.34@266.827,171.069 265.557,172.339
  Bottom Layer w0.3: v1@248.446,227.445 250.117,226.768 ; v1@248.976,228.164 250.117,226.768 ; v1@256.476,213.809 256.921,215.241 v1@257.366,213.809 ; v1@257.175,213.487 v1(256.921,213.741) 256.921,219.964 249.047,227.838 v1(248.666,227.838) 250.117,226.768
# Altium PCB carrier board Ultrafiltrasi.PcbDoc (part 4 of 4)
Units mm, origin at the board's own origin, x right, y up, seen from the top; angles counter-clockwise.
Board outline 216.53 x 247.52 mm, 2 copper layers (Top Layer, Bottom Layer); 114 components, 209 nets, 667 pads, 68 vias.
Unrouted connection lines stored in the file: 3.

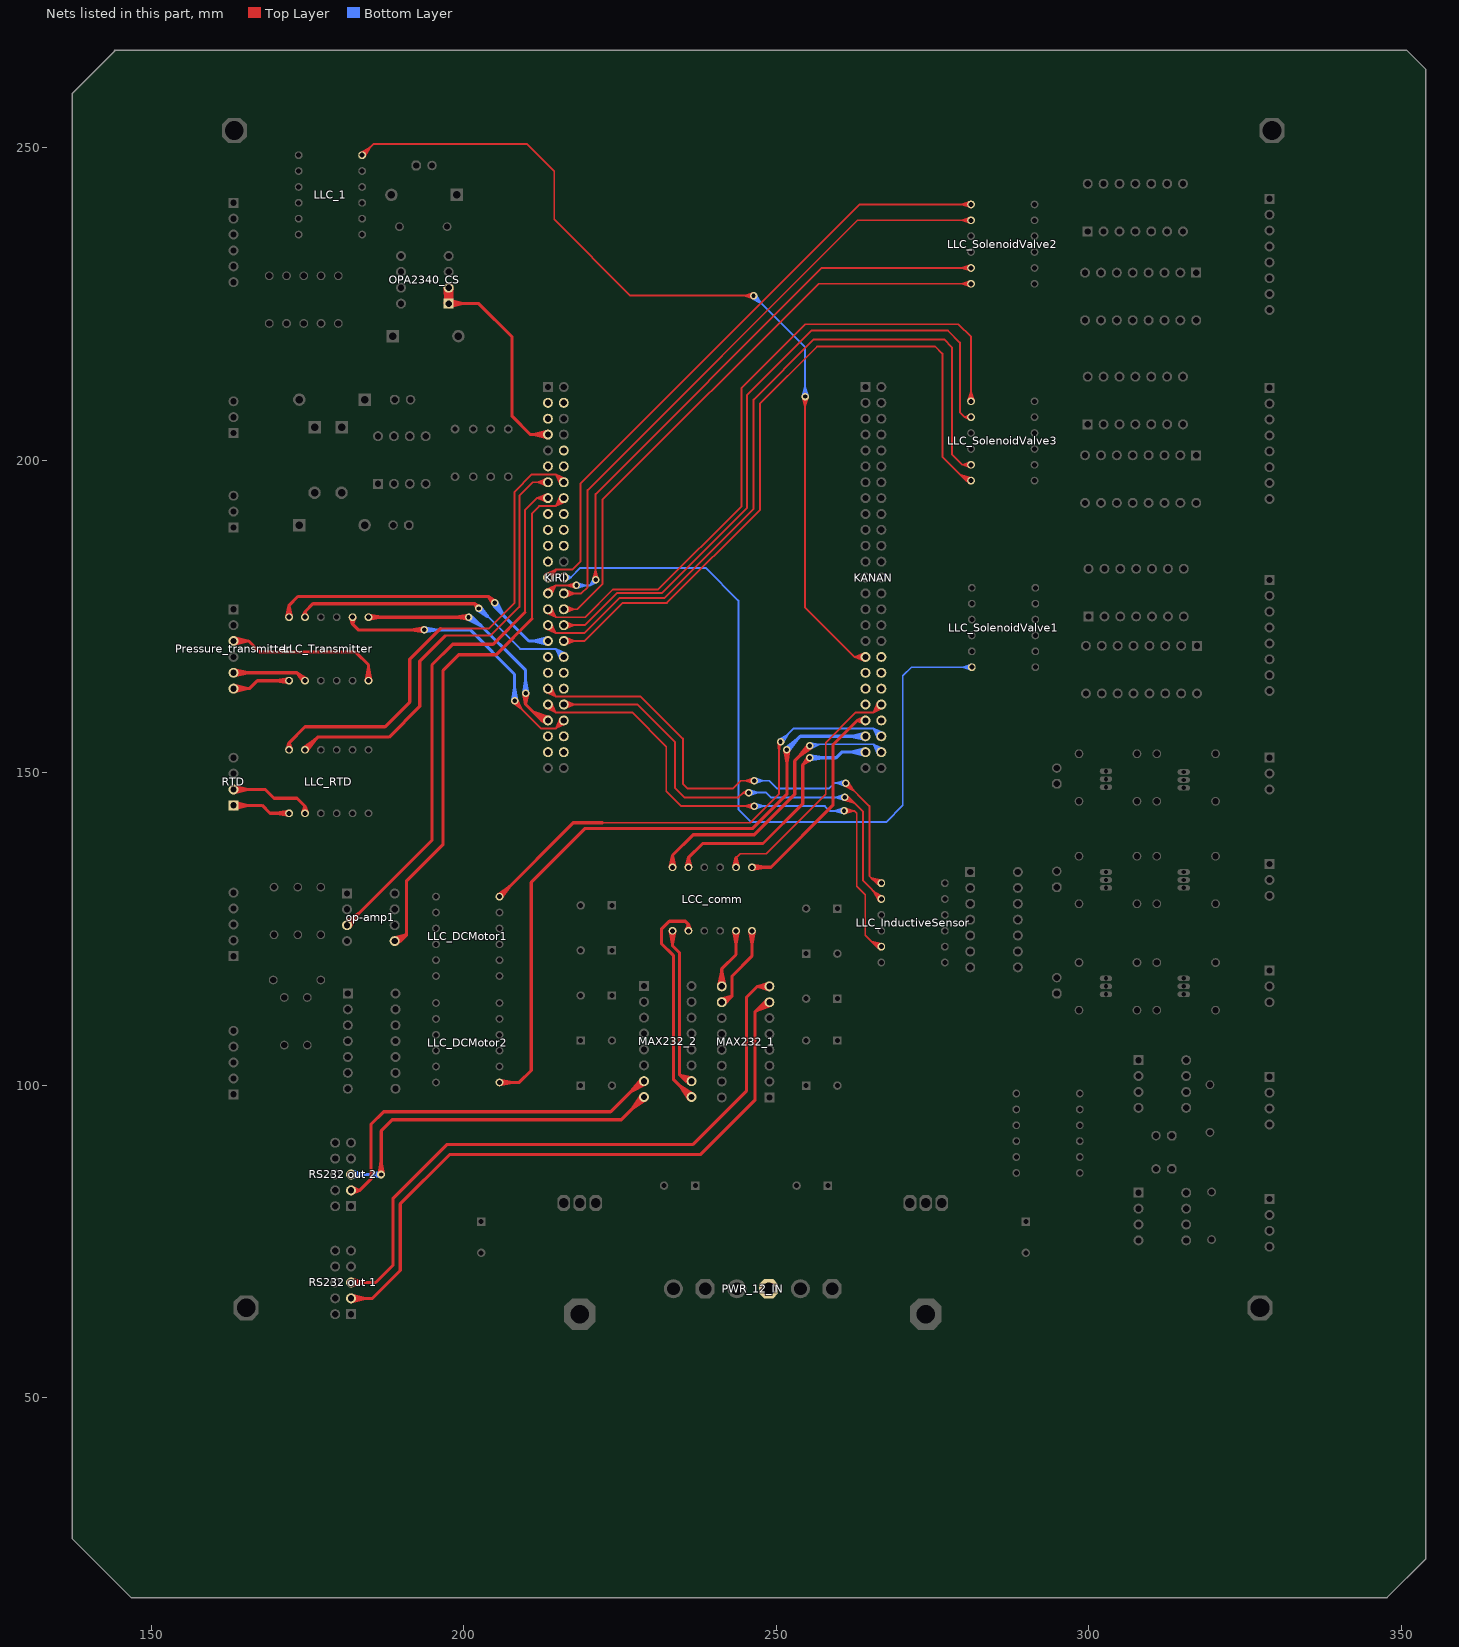
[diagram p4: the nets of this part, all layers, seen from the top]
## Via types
v1: diameter 1.2, hole 0.711, Top Layer to Bottom Layer, 27 vias
v2: diameter 1.27, hole 0.711, Top Layer to Bottom Layer, 21 vias
v3: diameter 1.2, hole 0.7, Top Layer to Bottom Layer, 19 vias
v4: diameter 1.5, hole 0.8, Top Layer to Bottom Layer, 1 vias

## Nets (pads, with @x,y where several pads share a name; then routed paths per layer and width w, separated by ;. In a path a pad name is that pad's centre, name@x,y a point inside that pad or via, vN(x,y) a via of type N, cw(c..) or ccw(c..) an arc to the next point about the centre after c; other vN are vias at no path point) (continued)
NetKANAN_35: KANAN.35 LLC_1.P$6 | length 174.8
  Top Layer w0.3: LLC_1.P$6@183.481,249.171 185.03,250.054 ; LLC_1.P$6@183.651,248.923 185.03,250.054 ; LLC_1.P$6@183.769,248.793 185.547,250.571 210.185,250.571 214.503,246.253 214.503,238.506 226.695,226.314 v1@246.062,226.314 ; LLC_1.P$6@183.899,248.675 185.03,250.054 ; LLC_1.P$6@184.147,248.505 185.03,250.054 ; v1@246.312,225.869 244.88,226.314 ; v1@246.312,226.759 244.88,226.314 ; v1(246.38,226.314) 244.88,226.314 ; v1@254.19,210.117 254.635,208.685 ; v1(254.635,210.185) 254.635,208.685 ; v1@254.635,210.693 254.635,176.403 262.509,168.529 KANAN.35@264.287,168.529 ; v1@255.08,210.117 254.635,208.685 ; KANAN.35@264.163,167.891 262.587,168.529 ; KANAN.35@264.163,169.167 262.587,168.529 ; KANAN.35@264.251,168.181 262.587,168.529 ; KANAN.35@264.251,168.877 262.587,168.529
  Bottom Layer w0.3: v1@246.105,225.958 247.616,225.078 v1@246.736,226.589 ; v1(246.38,226.314) 254.635,218.059 v1@254.635,210.693 ; v1@254.19,210.253 254.635,211.685 ; v1(254.635,210.185) 254.635,211.685 ; v1@255.08,210.253 254.635,211.685
NetKANAN_36: KANAN.36
NetKANAN_37: KANAN.37
NetKANAN_38: KANAN.38
NetKANAN_39: KANAN.39
NetKANAN_40: KANAN.40
NetKANAN_41: KANAN.41
NetKANAN_42: KANAN.42 LCC_comm.P$2 | length 51.8
  Top Layer w0.3: 243.586,136.398 244.221,137.033 248.412,137.033 257.937,146.558 257.937,154.813 262.763,159.639 265.557,159.639 ; KANAN.42@266.292,161.278 265.557,159.639 ; KANAN.42@266.557,161.131 265.557,159.639 ; KANAN.42@267.049,160.639 265.557,159.639 ; KANAN.42@267.196,160.374 265.557,159.639 ; 265.557,159.639 KANAN.42@266.827,160.909 265.557,159.639
  Top Layer w0.5: LCC_comm.P$2@243.214,134.92 243.586,136.398 ; LCC_comm.P$2@243.586,134.874 243.586,136.398 ; LCC_comm.P$2@243.958,134.92 243.586,136.398
NetKANAN_43: KANAN.43 LCC_comm.P$1 | length 41.6
  Top Layer w0.5: LCC_comm.P$1@246.126,134.874 249.174,134.874 259.08,144.78 259.08,154.432 263.017,158.369 ; LCC_comm.P$1@246.159,134.5 248.251,134.874 LCC_comm.P$1@246.159,135.248 ; KANAN.43@264.168,157.832 263.017,158.369 ; KANAN.43@264.168,158.906 263.017,158.369 ; 263.017,158.369 KANAN.43@264.287,158.369 263.017,158.369
NetKANAN_44: KANAN.44
NetKANAN_45: KANAN.45 LLC_DCMotor2.P$1 | length 121
  Top Layer w0.5: LLC_DCMotor2.P$1@205.74,100.457 208.915,100.457 210.82,102.362 210.82,132.461 219.456,141.097 246.253,141.097 251.714,146.558 v3(251.714,153.67) ; LLC_DCMotor2.P$1@205.773,100.083 207.865,100.457 LLC_DCMotor2.P$1@205.773,100.831 ; v3@251.365,153.641 251.714,151.57 v3@252.063,153.641
  Bottom Layer w0.5: v3@251.486,153.935 253.375,155.331 v3@251.979,153.442 ; v3(251.714,153.67) 253.873,155.829 KANAN.45@264.287,155.829 ; KANAN.45@264.221,155.283 261.987,155.829 KANAN.45@264.221,156.375
NetKANAN_46: KANAN.46 LLC_DCMotor1.P$6 | length 97.8
  Top Layer w0.3: 222.25,141.986 245.872,141.986 250.444,146.558 250.444,154.686 v1(250.698,154.94) 250.444,153.367 v1@250.248,154.948
  Top Layer w0.5: LLC_DCMotor1.P$6@205.497,130.46 207.426,131.861 LLC_DCMotor1.P$6@206.025,129.932 ; LLC_DCMotor1.P$6@205.74,130.175 217.551,141.986 222.25,141.986
  Bottom Layer w0.3: v1@250.423,155.296 251.934,156.176 v1@251.054,154.665 ; v1(250.698,154.94) 252.837,157.079 265.577,157.079 ; KANAN.46@266.291,155.462 265.577,157.079 ; KANAN.46@266.556,155.607 265.577,157.079 ; KANAN.46@267.049,156.1 265.577,157.079 ; KANAN.46@267.194,156.365 265.577,157.079 ; 265.577,157.079 KANAN.46@266.827,155.829 265.577,157.079
NetKANAN_47: KANAN.47 LCC_comm.P$5 | length 57.3
  Top Layer w0.5: LCC_comm.P$5@235.594,134.92 235.966,136.398 ; LCC_comm.P$5@235.966,134.874 235.966,136.398 ; LCC_comm.P$5@236.338,134.92 235.966,136.398 ; v3@255.124,152.619 254.254,151.257 ; v3@255.27,152.273 254.254,151.257 ; v3@255.397,152.146 v3(255.397,152.4) 254.254,151.257 ; v3@255.616,152.127 254.254,151.257 ; 235.966,136.398 238.252,138.684 247.904,138.684 254.254,145.034 254.254,151.257
  Bottom Layer w0.5: v3(255.397,152.4) 259.588,152.4 260.477,153.289 KANAN.47@264.287,153.289 ; v3@255.426,152.051 257.497,152.4 v3@255.426,152.749 ; KANAN.47@264.221,152.743 261.987,153.289 KANAN.47@264.221,153.835
NetKANAN_48: KANAN.48 LCC_comm.P$6 | length 70.9
  Top Layer w0.5: LCC_comm.P$6@233.053,134.911 233.426,136.779 ; LCC_comm.P$6@233.426,134.874 233.426,136.779 ; LCC_comm.P$6@233.799,134.911 233.426,136.779 ; v3@255.132,154.533 253.736,152.644 ; v3@255.625,154.04 253.736,152.644 ; 233.426,136.779 236.728,140.081 246.507,140.081 252.984,146.558 252.984,151.892 v3(255.397,154.305) 253.736,152.644
  Bottom Layer w0.3: v3@255.389,154.755 256.972,154.559 ; v3@255.531,153.875 256.972,154.559 ; KANAN.48@266.292,152.92 265.557,154.559 ; KANAN.48@266.557,153.067 265.557,154.559 ; KANAN.48@267.049,153.559 265.557,154.559 ; KANAN.48@267.196,153.824 265.557,154.559 ; 256.972,154.559 v3(255.397,154.305) 255.651,154.559 265.557,154.559 ; 265.557,154.559 KANAN.48@266.827,153.289 265.557,154.559
NetKIRI_3: KIRI.3 KIRI.4
NetKIRI_5: KIRI.5
NetKIRI_7: KIRI.7 OPA2340_CS.1 OPA2340_CS.2 | length 66.9
  Top Layer w0.5: OPA2340_CS.2@197.065,227.637 OPA2340_CS.1@197.116,225.317 ; OPA2340_CS.1@197.066,225.11 197.612,227.344 OPA2340_CS.1@198.158,225.11 ; OPA2340_CS.2@197.066,227.518 197.612,225.284 OPA2340_CS.2@198.158,227.518 ; OPA2340_CS.2@197.092,227.404 OPA2340_CS.1@198.108,225.317 ; OPA2340_CS.1@197.678,224.498 199.912,225.044 OPA2340_CS.1@197.678,225.59 ; OPA2340_CS.2@198.132,227.404 OPA2340_CS.1@197.116,225.317 ; OPA2340_CS.2@198.159,227.637 OPA2340_CS.1@198.108,225.317 ; KIRI.7@213.421,203.543 211.187,204.089 KIRI.7@213.421,204.635 ; KIRI.7@213.487,204.089 210.693,204.089 207.772,207.01 207.772,219.71 202.438,225.044 OPA2340_CS.1@197.612,225.044 OPA2340_CS.2@197.612,227.584 ; OPA2340_CS.1@197.116,225.317 OPA2340_CS.2@197.612,227.584 ; OPA2340_CS.2@197.612,227.584 OPA2340_CS.1@198.108,225.317
NetKIRI_10: KIRI.10
NetKIRI_11: KIRI.11
NetKIRI_12: KIRI.12
NetKIRI_13: KIRI.13 LLC_RTD.P$5 | length 82.8
  Top Layer w0.3: 197.04,171.958 204.343,171.958 208.915,176.53 208.915,194.31 211.074,196.469 KIRI.13@213.487,196.469 ; KIRI.13@213.363,195.831 211.787,196.469 ; KIRI.13@213.363,197.107 211.787,196.469 ; KIRI.13@213.451,196.121 211.787,196.469 ; KIRI.13@213.451,196.817 211.787,196.469
  Top Layer w0.5: LLC_RTD.P$5@174.382,153.955 176.311,155.356 LLC_RTD.P$5@174.91,153.427 ; LLC_RTD.P$5@174.625,153.67 176.657,155.702 188.087,155.702 192.992,160.607 192.992,167.846 197.04,171.894
NetKIRI_14: KIRI.14 LLC_RTD.P$6 | length 88.9
  Top Layer w0.3: 196.342,173.101 204.089,173.101 208.153,177.165 208.153,194.945 210.927,197.719 214.777,197.719 ; KIRI.14@215.491,196.102 214.777,197.719 ; KIRI.14@215.756,196.247 214.777,197.719 ; KIRI.14@216.249,196.74 214.777,197.719 ; KIRI.14@216.394,197.005 214.777,197.719 ; 214.777,197.719 KIRI.14@216.027,196.469 214.777,197.719
  Top Layer w0.5: LLC_RTD.P$6@171.715,153.732 172.085,154.813 ; LLC_RTD.P$6@172.085,153.67 172.085,154.813 ; LLC_RTD.P$6@172.455,153.732 172.085,154.813 ; 196.342,173.101 191.389,168.148 191.389,161.29 187.452,157.353 174.625,157.353 172.085,154.813
NetKIRI_15: KIRI.15 op-amp1.3 | length 98.5
  Top Layer w0.3: 209.804,175.641 209.804,192.024 211.709,193.929 KIRI.15@213.487,193.929 ; KIRI.15@213.363,193.291 211.787,193.929 ; KIRI.15@213.363,194.567 211.787,193.929 ; KIRI.15@213.451,193.581 211.787,193.929 ; KIRI.15@213.451,194.277 211.787,193.929
  Top Layer w0.5: op-amp1.3@181.01,126.03 183.217,127.464 op-amp1.3@181.783,125.257 ; op-amp1.3@181.356,125.603 194.945,139.192 194.945,167.259 198.247,170.561 204.724,170.561 209.804,175.641
NetKIRI_16: KIRI.16 op-amp1.5 | length 107.6
  Top Layer w0.3: 210.947,174.625 210.947,191.516 212.09,192.659 213.868,192.659 213.888,192.679 214.737,192.679 ; KIRI.16@215.498,194.306 214.737,192.679 ; KIRI.16@215.76,194.155 214.737,192.679 ; KIRI.16@216.245,193.655 214.737,192.679 ; KIRI.16@216.387,193.388 214.737,192.679 ; 214.737,192.679 KIRI.16@216.027,193.929 215.987,193.929 214.737,192.679
  Top Layer w0.5: op-amp1.5@188.781,123.577 190.881,124.079 ; op-amp1.5@189.295,122.615 190.881,124.079 ; 210.947,174.625 205.2,168.878 199.231,168.878 196.723,166.37 196.723,138.557 190.881,132.715 190.881,124.079 ; op-amp1.5@188.976,123.063 189.865,123.063 ; op-amp1.5@188.976,123.063 190.881,124.079 ; op-amp1.5@188.976,123.063 189.865,123.063 ; 189.865,123.063 189.146,122.54 189.865,123.063 ; 189.865,123.063 189.146,123.586 189.865,123.063 ; 189.865,123.063 190.881,124.079
NetKIRI_17: KIRI.17
NetKIRI_18: KIRI.18
NetKIRI_19: KIRI.19
NetKIRI_20: KIRI.20
NetKIRI_21: KIRI.21
NetKIRI_22: KIRI.22
NetKIRI_23: KIRI.23
NetKIRI_25: KIRI.25 LLC_SolenoidValve2.P$1 | length 113.1
  Top Layer w0.3: KIRI.25@213.117,181.763 214.777,182.519 ; KIRI.25@213.264,181.499 214.777,182.519 ; KIRI.25@213.487,181.229 214.777,182.519 ; KIRI.25@213.757,181.006 214.777,182.519 ; KIRI.25@214.021,180.859 214.777,182.519 ; LLC_SolenoidValve2.P$1@281.104,240.45 279.653,240.919 ; LLC_SolenoidValve2.P$1@281.104,241.388 279.653,240.919 ; LLC_SolenoidValve2.P$1@281.168,240.744 279.653,240.919 ; LLC_SolenoidValve2.P$1@281.168,241.094 279.653,240.919 ; LLC_SolenoidValve2.P$1@281.178,240.919 263.398,240.919 218.694,196.215 218.694,183.769 217.444,182.519 214.777,182.519
NetKIRI_26: KIRI.26 LLC_SolenoidValve1.P$6 | length 135.4
  Bottom Layer w0.3: KIRI.26@216.027,181.229 217.17,181.229 ; KIRI.26@216.081,180.883 217.17,181.229 ; KIRI.26@216.081,181.575 217.17,181.229 ; KIRI.26@216.212,180.606 217.17,181.229 ; KIRI.26@216.212,181.852 217.17,181.229 ; LLC_SolenoidValve1.P$6@281.231,166.409 279.78,166.878 ; LLC_SolenoidValve1.P$6@281.231,167.347 279.78,166.878 ; LLC_SolenoidValve1.P$6@281.295,166.703 279.78,166.878 ; LLC_SolenoidValve1.P$6@281.295,167.053 279.78,166.878 ; LLC_SolenoidValve1.P$6@281.305,166.878 271.653,166.878 270.256,165.481 270.256,144.78 267.589,142.113 245.999,142.113 243.967,144.145 243.967,177.546 238.76,182.753 218.694,182.753 217.17,181.229
NetKIRI_27: KIRI.27 LLC_SolenoidValve2.P$5 | length 123.5
  Top Layer w0.3: KIRI.27@213.12,179.225 214.737,179.939 ; KIRI.27@213.265,178.96 214.737,179.939 ; KIRI.27@213.487,178.689 214.737,179.939 ; KIRI.27@213.758,178.467 214.737,179.939 ; KIRI.27@214.023,178.322 214.737,179.939 ; v1@217.986,180.403 216.559,179.939 ; v1@217.997,179.513 216.559,179.939 ; v1@218.059,179.939 214.737,179.939 ; v1(218.059,179.959) 216.559,179.939 ; v1@220.662,180.916 221.107,182.348 v1@221.552,180.916 ; v1(221.107,180.848) 221.107,194.564 257.302,230.759 LLC_SolenoidValve2.P$5@281.178,230.759 ; LLC_SolenoidValve2.P$5@281.104,230.29 279.653,230.759 ; LLC_SolenoidValve2.P$5@281.104,231.228 279.653,230.759 ; LLC_SolenoidValve2.P$5@281.168,230.584 279.653,230.759 ; LLC_SolenoidValve2.P$5@281.168,230.934 279.653,230.759
  Bottom Layer w0.3: v1(218.059,179.959) 220.218,179.959 ; v1@218.127,179.514 219.559,179.959 v1@218.127,180.404 ; v1@220.737,181.104 220.218,179.959 ; v1(221.107,180.848) 220.218,179.959 ; v1@221.363,180.478 220.218,179.959
NetKIRI_28: KIRI.28 LLC_SolenoidValve2.P$2 | length 111.9
  Top Layer w0.3: KIRI.28@216.027,178.689 218.821,178.689 219.837,179.705 219.837,195.199 263.017,238.379 LLC_SolenoidValve2.P$2@281.178,238.379 ; KIRI.28@216.063,178.341 217.727,178.689 ; KIRI.28@216.063,179.037 217.727,178.689 ; KIRI.28@216.151,178.051 217.727,178.689 ; KIRI.28@216.151,179.327 217.727,178.689 ; LLC_SolenoidValve2.P$2@281.104,237.91 279.653,238.379 ; LLC_SolenoidValve2.P$2@281.104,238.848 279.653,238.379 ; LLC_SolenoidValve2.P$2@281.168,238.204 279.653,238.379 ; LLC_SolenoidValve2.P$2@281.168,238.554 279.653,238.379
NetKIRI_29: KIRI.29 LLC_SolenoidValve3.P$1 | length 123.1
  Top Layer w0.3: KIRI.29@213.118,175.614 214.757,174.879 ; KIRI.29@213.265,175.879 214.757,174.879 ; KIRI.29@213.487,176.149 214.757,174.879 ; KIRI.29@213.757,176.371 214.757,174.879 ; KIRI.29@214.022,176.518 214.757,174.879 ; LLC_SolenoidValve3.P$1@280.709,209.497 281.178,210.948 ; LLC_SolenoidValve3.P$1@281.003,209.433 281.178,210.948 ; LLC_SolenoidValve3.P$1@281.178,209.423 281.178,219.71 279.146,221.742 254.635,221.742 244.475,211.582 244.475,192.659 231.14,179.324 223.901,179.324 219.456,174.879 214.757,174.879 ; LLC_SolenoidValve3.P$1@281.353,209.433 281.178,210.948 ; LLC_SolenoidValve3.P$1@281.647,209.497 281.178,210.948
NetKIRI_30: KIRI.30 LLC_SolenoidValve2.P$6 | length 107.5
  Top Layer w0.3: KIRI.30@216.027,176.149 218.186,176.149 222.215,180.178 222.215,193.64 256.794,228.219 LLC_SolenoidValve2.P$6@281.178,228.219 ; KIRI.30@216.063,175.801 217.727,176.149 ; KIRI.30@216.063,176.497 217.727,176.149 ; KIRI.30@216.151,175.511 217.727,176.149 ; KIRI.30@216.151,176.787 217.727,176.149 ; LLC_SolenoidValve2.P$6@281.104,227.75 279.653,228.219 ; LLC_SolenoidValve2.P$6@281.104,228.688 279.653,228.219 ; LLC_SolenoidValve2.P$6@281.168,228.044 279.653,228.219 ; LLC_SolenoidValve2.P$6@281.168,228.394 279.653,228.219
NetKIRI_31: KIRI.31 LLC_SolenoidValve3.P$5 | length 130.3
  Top Layer w0.3: KIRI.31@213.12,173.073 214.737,172.359 ; KIRI.31@213.265,173.338 214.737,172.359 ; KIRI.31@213.487,173.609 214.737,172.359 ; KIRI.31@213.758,173.831 214.737,172.359 ; KIRI.31@214.023,173.976 214.737,172.359 ; LLC_SolenoidValve3.P$5@281.097,198.795 279.781,199.263 ; LLC_SolenoidValve3.P$5@281.097,199.731 279.781,199.263 ; LLC_SolenoidValve3.P$5@281.167,199.088 279.781,199.263 ; LLC_SolenoidValve3.P$5@281.167,199.438 279.781,199.263 ; 214.737,172.359 219.349,172.359 224.917,177.927 232.116,177.927 246.38,192.191 246.38,209.677 256.032,219.329 276.86,219.329 278.13,218.059 278.13,200.914 279.781,199.263 ; 279.781,199.263 LLC_SolenoidValve3.P$5@281.178,199.263 279.781,199.263
NetKIRI_32: KIRI.32 LLC_SolenoidValve3.P$2 | length 118.4
  Top Layer w0.3: KIRI.32@216.027,173.609 219.416,173.609 224.531,178.724 231.683,178.724 245.364,192.405 245.364,210.439 255.651,220.726 277.495,220.726 279.4,218.821 279.4,207.645 280.162,206.883 ; KIRI.32@216.063,173.261 217.727,173.609 ; KIRI.32@216.063,173.957 217.727,173.609 ; KIRI.32@216.151,172.971 217.727,173.609 ; KIRI.32@216.151,174.247 217.727,173.609 ; LLC_SolenoidValve3.P$2@281.067,206.421 280.162,206.883 ; LLC_SolenoidValve3.P$2@281.067,207.345 280.162,206.883 ; LLC_SolenoidValve3.P$2@281.163,206.709 280.162,206.883 ; LLC_SolenoidValve3.P$2@281.163,207.057 280.162,206.883 ; LLC_SolenoidValve3.P$2@281.178,206.883 280.162,206.883
NetKIRI_33: KIRI.33 LLC_Transmitter.P$6 | length 70.4
  Top Layer w0.5: LLC_Transmitter.P$6@171.712,174.916 172.085,176.784 ; LLC_Transmitter.P$6@172.085,174.879 172.085,176.784 ; LLC_Transmitter.P$6@172.458,174.916 172.085,176.784 ; v3@204.702,176.949 203.962,178.181 ; v3@205.194,177.441 203.962,178.181 ; 172.085,176.784 173.482,178.181 203.962,178.181 ; 203.962,178.181 v3(204.978,177.165) 203.962,178.181
  Bottom Layer w0.5: v3@204.704,176.947 206.358,175.15 ; v3@205.28,177.342 206.358,175.15 ; KIRI.33@213.421,170.523 211.187,171.069 KIRI.33@213.421,171.615 ; KIRI.33@213.487,171.069 210.439,171.069 204.978,176.53 ; 204.978,176.53 v3(204.978,177.165) ; 204.978,176.53 204.642,177.069 204.978,176.53 ; 204.978,176.53 205.314,177.069 204.978,176.53 ; 204.978,176.53 v3(204.978,177.165) ; v3(204.978,177.165) 206.358,175.15
NetKIRI_34: KIRI.34 LLC_SolenoidValve3.P$6 | length 136.4
  Top Layer w0.3: KIRI.34@216.027,171.069 219.329,171.069 225.425,177.165 232.537,177.165 247.396,192.024 247.396,209.042 256.54,218.186 275.463,218.186 276.606,217.043 276.606,200.533 280.416,196.723 ; KIRI.34@216.063,170.721 217.727,171.069 ; KIRI.34@216.063,171.417 217.727,171.069 ; KIRI.34@216.151,170.431 217.727,171.069 ; KIRI.34@216.151,171.707 217.727,171.069 ; LLC_SolenoidValve3.P$6@280.9,196.338 279.5,197.639 ; LLC_SolenoidValve3.P$6@281.087,196.573 279.5,197.639 ; LLC_SolenoidValve3.P$6@281.255,196.88 279.5,197.639 ; LLC_SolenoidValve3.P$6@281.352,197.165 279.5,197.639 ; 279.5,197.639 LLC_SolenoidValve3.P$6@281.178,196.723 ; 280.416,196.723 LLC_SolenoidValve3.P$6@281.178,196.723 ; 280.416,196.723 281.158,196.897 280.416,196.723 ; 280.416,196.723 281.158,196.549 280.416,196.723 ; 280.416,196.723 281.03,197.174 280.416,196.723 ; 280.416,196.723 281.03,196.272 280.416,196.723 ; 280.416,196.723 LLC_SolenoidValve3.P$6@281.178,196.723
NetKIRI_35: KIRI.35
NetKIRI_36: KIRI.36 LLC_Transmitter.P$5 | length 65.7
  Top Layer w0.5: LLC_Transmitter.P$5@174.258,174.958 174.625,175.768 ; LLC_Transmitter.P$5@174.625,174.879 174.625,175.768 ; LLC_Transmitter.P$5@174.992,174.958 174.625,175.768 ; v3@202.134,176.103 201.803,177.038 ; v3(202.438,176.276) 201.803,177.038 ; v3@202.438,176.403 201.803,177.038 ; v3@202.663,176.544 201.803,177.038 ; 174.625,175.768 175.895,177.038 201.803,177.038
  Bottom Layer w0.3: 203.835,175.006 209.042,169.799 214.757,169.799 ; KIRI.36@215.492,168.16 214.757,169.799 ; KIRI.36@215.757,168.307 214.757,169.799 ; KIRI.36@216.249,168.799 214.757,169.799 ; KIRI.36@216.396,169.064 214.757,169.799 ; 214.757,169.799 KIRI.36@216.027,168.529 214.757,169.799
  Bottom Layer w0.5: v3@202.228,175.996 203.835,175.006 ; v3(202.438,176.276) 203.835,175.006 ; v3@202.438,176.403 203.835,175.006 ; v3@202.696,176.512 203.835,175.006
NetKIRI_37: KIRI.37
NetKIRI_38: KIRI.38
NetKIRI_39: KIRI.39 LLC_InductiveSensor.P$1 | length 116.7
  Top Layer w0.3: KIRI.39@213.118,162.914 214.757,162.179 ; KIRI.39@213.265,163.179 214.757,162.179 ; KIRI.39@213.487,163.449 214.757,162.179 ; KIRI.39@213.757,163.671 214.757,162.179 ; KIRI.39@214.022,163.818 214.757,162.179 ; v1@246.439,148.272 245.007,148.717 v1@246.439,149.162 ; v1(246.507,148.717) 244.348,148.717 243.078,147.447 235.839,147.447 235.077,148.209 235.077,155.448 228.346,162.179 214.757,162.179 ; v1@260.856,147.966 262.404,147.171 ; v1(261.112,148.336) 262.404,147.171 ; v1@261.175,148.399 264.922,144.653 264.922,133.477 266.065,132.334 ; v1@261.454,148.628 262.404,147.171 ; LLC_InductiveSensor.P$1@266.554,131.945 265.248,133.151 ; LLC_InductiveSensor.P$1@266.739,132.183 265.248,133.151 ; LLC_InductiveSensor.P$1@266.9,132.493 265.248,133.151 ; LLC_InductiveSensor.P$1@266.987,132.781 265.248,133.151 ; 265.248,133.151 LLC_InductiveSensor.P$1@266.827,132.334 ; 266.065,132.334 LLC_InductiveSensor.P$1@266.827,132.334 ; 266.065,132.334 266.807,132.508 266.065,132.334 ; 266.065,132.334 266.807,132.16 266.065,132.334 ; 266.065,132.334 266.679,132.785 266.065,132.334 ; 266.065,132.334 266.679,131.883 266.065,132.334 ; 266.065,132.334 LLC_InductiveSensor.P$1@266.827,132.334 ; 266.065,132.334 LLC_InductiveSensor.P$1@266.827,132.334
  Bottom Layer w0.3: v1(246.507,148.717) 248.92,148.717 250.19,147.447 258.445,147.447 259.334,148.336 v1(261.112,148.336) ; v1@246.575,148.272 248.007,148.717 v1@246.575,149.162 ; v1@261.044,147.891 259.612,148.336 v1@261.044,148.781
NetKIRI_40: KIRI.40
NetKIRI_41: KIRI.41 LLC_InductiveSensor.P$5 | length 120.9
  Top Layer w0.3: KIRI.41@213.118,160.374 214.757,159.639 ; KIRI.41@213.265,160.639 214.757,159.639 ; KIRI.41@213.487,160.909 214.757,159.639 ; KIRI.41@213.757,161.131 214.757,159.639 ; KIRI.41@214.022,161.278 214.757,159.639 ; v1@246.439,144.208 245.007,144.653 ; v1@246.439,145.098 245.007,144.653 ; v1(260.858,143.891) 262.509,143.891 262.89,143.51 262.89,131.826 264.255,130.461 264.255,123.984 266.065,122.174 ; v1@260.926,143.446 262.358,143.891 v1@260.926,144.336 ; LLC_InductiveSensor.P$5@266.552,121.787 265.204,123.035 ; LLC_InductiveSensor.P$5@266.738,122.023 265.204,123.035 ; LLC_InductiveSensor.P$5@266.902,122.332 265.204,123.035 ; LLC_InductiveSensor.P$5@266.993,122.619 265.204,123.035 ; 214.757,159.639 226.949,159.639 232.41,154.178 232.41,147.066 234.823,144.653 v1(246.507,144.653) 245.007,144.653 ; 265.204,123.035 LLC_InductiveSensor.P$5@266.827,122.174 ; 266.065,122.174 LLC_InductiveSensor.P$5@266.827,122.174 ; 266.065,122.174 266.807,122.348 266.065,122.174 ; 266.065,122.174 266.807,122 266.065,122.174 ; 266.065,122.174 266.679,122.625 266.065,122.174 ; 266.065,122.174 266.679,121.723 266.065,122.174 ; 266.065,122.174 LLC_InductiveSensor.P$5@266.827,122.174
  Bottom Layer w0.3: v1(246.507,144.653) 257.81,144.653 258.572,143.891 v1(260.858,143.891) ; v1@246.575,144.208 248.007,144.653 v1@246.575,145.098 ; v1@260.79,143.446 259.358,143.891 v1@260.79,144.336
NetKIRI_42: KIRI.42 LLC_InductiveSensor.P$2 | length 106.3
  Top Layer w0.3: KIRI.42@216.027,160.909 227.838,160.909 233.807,154.94 233.807,147.574 235.331,146.05 243.967,146.05 244.729,146.812 ; KIRI.42@216.063,160.561 217.727,160.909 ; KIRI.42@216.063,161.257 217.727,160.909 ; KIRI.42@216.151,160.271 217.727,160.909 ; KIRI.42@216.151,161.547 217.727,160.909 ; v1@245.504,146.377 244.729,146.812 ; v1@245.504,147.247 244.729,146.812 ; v1@260.807,145.637 262.53,145.14 ; v1@261.26,146.406 262.53,145.14 ; LLC_InductiveSensor.P$2@266.449,129.506 265.566,131.055 ; LLC_InductiveSensor.P$2@266.697,129.676 265.566,131.055 ; LLC_InductiveSensor.P$2@266.827,129.794 263.906,132.715 263.906,143.764 261.62,146.05 ; LLC_InductiveSensor.P$2@266.945,129.924 265.566,131.055 ; LLC_InductiveSensor.P$2@267.115,130.172 265.566,131.055 ; 244.729,146.812 v1(245.618,146.812) 244.729,146.812 ; v1(260.985,146.05) 261.62,146.05 ; v1(260.985,146.05) 262.53,145.14 ; v1(260.985,146.05) 261.62,146.05 ; 261.62,146.05 261.144,145.629 261.62,146.05 ; 261.62,146.05 261.144,146.471 261.62,146.05
  Bottom Layer w0.3: v1(245.618,146.812) 248.412,146.812 249.174,146.05 v1(260.985,146.05) ; v1@245.686,146.367 247.118,146.812 v1@245.686,147.257 ; v1@260.917,145.605 259.485,146.05 v1@260.917,146.495
NetKIRI_43: KIRI.43 LLC_Transmitter.P$1 | length 81.5
  Top Layer w0.5: LLC_Transmitter.P$1@184.785,174.879 v3(200.787,174.879) ; LLC_Transmitter.P$1@184.818,174.505 186.91,174.879 LLC_Transmitter.P$1@184.818,175.253 ; v3@200.758,174.53 198.687,174.879 v3@200.758,175.228 ; v1@209.583,162.653 209.931,160.909 ; v1@210.279,162.653 209.931,160.909 ; KIRI.43@213.168,157.921 211.128,159.712 ; KIRI.43@213.709,158.872 211.128,159.712 ; 209.931,160.909 v1(209.931,162.687) 209.931,160.909 ; 209.931,160.909 212.471,158.369 ; 211.128,159.712 KIRI.43@213.487,158.369 ; 212.471,158.369 KIRI.43@213.487,158.369 ; 212.471,158.369 213.338,158.898 212.471,158.369 ; 212.471,158.369 213.338,157.84 212.471,158.369 ; 212.471,158.369 KIRI.43@213.487,158.369 ; 212.471,158.369 KIRI.43@213.487,158.369
  Bottom Layer w0.5: v3@200.61,174.577 202.816,173.485 ; v3@201.005,175.153 202.816,173.485 ; v1@209.582,162.716 209.931,164.787 v1@210.28,162.716 ; v1(209.931,162.687) 209.931,166.37 201.422,174.879 ; v3(200.787,174.879) 201.422,174.879 ; v3(200.787,174.879) 202.816,173.485 ; v3(200.787,174.879) 201.422,174.879 ; 201.422,174.879 200.883,174.543 201.422,174.879 ; 201.422,174.879 200.883,175.215 201.422,174.879
NetKIRI_44: KIRI.44 LLC_Transmitter.P$2 | length 76.6
  Top Layer w0.3: v1@207.843,161.218 209.258,160.185 ; v1(208.153,161.544) 209.258,160.185 ; v1@208.534,161.798 208.153,161.417 208.153,161.29 212.344,157.099 214.757,157.099 ; v1@208.536,161.781 209.258,160.185 ; KIRI.44@215.492,158.738 214.757,157.099 ; KIRI.44@215.757,158.591 214.757,157.099 ; KIRI.44@216.249,158.099 214.757,157.099 ; KIRI.44@216.396,157.834 214.757,157.099 ; 214.757,157.099 KIRI.44@216.027,158.369 214.757,157.099
  Top Layer w0.5: LLC_Transmitter.P$2@181.875,174.817 182.245,173.736 ; LLC_Transmitter.P$2@182.245,174.879 182.245,173.736 ; LLC_Transmitter.P$2@182.615,174.817 182.245,173.736 ; v3@193.646,172.498 191.575,172.847 ; v3@193.646,173.196 191.575,172.847 ; 182.245,173.736 183.134,172.847 v3(193.675,172.847) 191.575,172.847
  Bottom Layer w0.5: v3(193.675,172.847) 201.041,172.847 208.153,165.735 v1(208.153,161.544) ; v3@193.704,172.498 195.775,172.847 v3@193.704,173.196 ; v1@207.804,161.573 208.153,163.644 v1@208.502,161.573
NetKIRI_45: KIRI.45
NetKIRI_46: KIRI.46
NetKIRI_47: KIRI.47
NetKIRI_48: KIRI.48
NetLCC_comm_P$7: LCC_comm.P$7 MAX232_2.10 | length 40.5
  Top Layer w0.5: LCC_comm.P$7@233.052,124.681 233.426,122.589 ; LCC_comm.P$7@233.8,124.681 233.426,122.589 ; MAX232_2.10@236.155,100.204 234.569,101.668 ; MAX232_2.10@236.304,100.129 235.585,100.652 ; MAX232_2.10@236.304,101.175 235.585,100.652 ; MAX232_2.10@236.669,101.166 234.569,101.668 ; 233.426,122.589 LCC_comm.P$7@233.426,124.714 233.426,122.301 234.569,121.158 234.569,101.668 ; 234.569,101.668 MAX232_2.10@236.474,100.652 235.585,100.652 ; 234.569,101.668 235.585,100.652
NetLCC_comm_P$8: LCC_comm.P$8 MAX232_2.9 | length 44.9
  Top Layer w0.5: LCC_comm.P$8@235.597,124.783 235.966,125.73 ; LCC_comm.P$8@235.966,124.714 235.966,125.73 ; MAX232_2.9@236.053,97.758 234.588,99.93 ; LCC_comm.P$8@236.335,124.783 235.966,125.73 ; MAX232_2.9@236.812,98.546 234.588,99.93 ; 234.588,99.93 MAX232_2.9@236.474,98.112 236.406,98.112 233.553,100.965 233.553,120.777 231.648,122.682 231.648,124.968 232.918,126.238 235.458,126.238 235.966,125.73
NetLCC_comm_P$11: LCC_comm.P$11 MAX232_1.9 | length 18.7
  Top Layer w0.5: MAX232_1.9@240.754,115.89 241.3,118.124 MAX232_1.9@241.846,115.89 ; MAX232_1.9@241.3,115.824 241.3,118.618 243.586,120.904 LCC_comm.P$11@243.586,124.714 ; LCC_comm.P$11@243.212,124.681 243.586,122.589 LCC_comm.P$11@243.96,124.681
NetLCC_comm_P$12: LCC_comm.P$12 MAX232_1.10 | length 23.9
  Top Layer w0.5: MAX232_1.10@241.081,113.789 242.951,114.3 ; MAX232_1.10@241.652,112.861 242.951,114.3 ; LCC_comm.P$12@245.752,124.681 246.126,122.589 LCC_comm.P$12@246.5,124.681 ; LCC_comm.P$12@246.126,124.714 246.126,120.65 242.951,117.475 242.951,114.3 ; 242.951,114.3 MAX232_1.10@241.3,113.284 241.935,113.284 242.951,114.3
NetLLC_Transmitter_P$12: LLC_Transmitter.P$12 Pressure_transmitter.3 | length 34.6
  Top Layer w0.5: Pressure_transmitter.3@163.195,171.069 165.608,171.069 167.386,169.291 182.753,169.291 184.785,167.259 LLC_Transmitter.P$12@184.785,164.719 ; Pressure_transmitter.3@163.261,170.523 165.495,171.069 Pressure_transmitter.3@163.261,171.615 ; LLC_Transmitter.P$12@184.411,164.752 184.785,166.844 LLC_Transmitter.P$12@185.159,164.752
NetMAX232_1_7: "RS232 out 1.3" MAX232_1.7 | length 113.5
  Top Layer w0.5: 181.991,65.913 185.42,65.913 189.865,70.358 189.865,81.026 197.739,88.9 237.871,88.9 246.634,97.663 246.634,111.76 248.158,113.284 MAX232_1.7@248.92,113.284 246.719,111.845 ; 182.057,65.367 184.291,65.913 182.057,66.459 ; MAX232_1.7@248.573,113.71 246.719,111.845 ; MAX232_1.7@249.171,112.795 246.719,111.845
NetMAX232_1_8: "RS232 out 1.5" MAX232_1.8 | length 111.9
  Top Layer w0.5: 181.991,68.453 185.928,68.453 188.722,71.247 188.722,81.915 197.358,90.551 236.728,90.551 245.237,99.06 245.237,114.046 247.015,115.824 ; 182.057,67.907 184.291,68.453 182.057,68.999 ; MAX232_1.8@248.841,115.28 247.015,115.824 ; MAX232_1.8@248.841,116.368 247.015,115.824 ; 247.015,115.824 MAX232_1.8@248.92,115.824 247.015,115.824
NetMAX232_2_7: "RS232 out 2.3" MAX232_2.7 | length 70
  Top Layer w0.5: 181.991,83.185 183.388,83.185 ; 182.099,82.646 183.388,83.185 ; 182.099,83.724 183.388,83.185 ; MAX232_2.7@228.47,101.046 226.775,99.013 ; MAX232_2.7@229.148,100.187 226.775,99.013 ; 183.388,83.185 185.166,84.963 185.166,93.726 187.198,95.758 223.52,95.758 228.414,100.652 MAX232_2.7@228.854,100.652 226.775,99.013
NetMAX232_2_8: "RS232 out 2.5" MAX232_2.8 | length 77.1
  Top Layer w0.5: v2@186.434,85.76 186.817,87.86 v2@187.2,85.76 ; v2(186.817,85.725) 186.817,92.71 188.595,94.488 225.23,94.488 MAX232_2.8@228.854,98.112 226.993,96.251 ; MAX232_2.8@228.427,98.458 226.993,96.251 ; MAX232_2.8@229.2,97.685 226.993,96.251
  Bottom Layer w0.5: 181.991,85.725 v2(186.817,85.725) ; 182.057,85.179 184.291,85.725 182.057,86.271 ; v2@186.782,85.342 184.682,85.725 v2@186.782,86.108
NetPWR_12_IN_1: PWR_12_IN.1
NRX: LLC_RTD.P$8 RTD.2 | length 20.6
  Top Layer w0.5: RTD.2@163.195,147.32 168.275,147.32 169.672,145.923 173.355,145.923 174.625,144.653 ; RTD.2@163.261,146.774 165.495,147.32 RTD.2@163.261,147.866 ; LLC_RTD.P$8@174.255,143.572 174.625,144.653 ; LLC_RTD.P$8@174.625,143.51 174.625,144.653 ; LLC_RTD.P$8@174.995,143.572 174.625,144.653
NTX: LLC_RTD.P$7 RTD.1 | length 18.3
  Top Layer w0.5: RTD.1@163.195,144.78 167.767,144.78 169.037,143.51 LLC_RTD.P$7@172.085,143.51 ; RTD.1@163.261,144.234 165.495,144.78 RTD.1@163.261,145.326 ; LLC_RTD.P$7@172.052,143.136 169.96,143.51 LLC_RTD.P$7@172.052,143.884
RXD_5V: LLC_Transmitter.P$7 Pressure_transmitter.6 | length 18.3
  Top Layer w0.5: Pressure_transmitter.6@163.195,163.449 165.735,163.449 167.005,164.719 LLC_Transmitter.P$7@172.085,164.719 ; Pressure_transmitter.6@163.261,162.903 165.495,163.449 Pressure_transmitter.6@163.261,163.995 ; LLC_Transmitter.P$7@172.052,164.345 169.96,164.719 LLC_Transmitter.P$7@172.052,165.093
TXD_5V: LLC_Transmitter.P$8 Pressure_transmitter.5 | length 21.9
  Top Layer w0.5: Pressure_transmitter.5@163.195,165.989 173.355,165.989 ; Pressure_transmitter.5@163.261,165.443 165.495,165.989 Pressure_transmitter.5@163.261,166.535 ; LLC_Transmitter.P$8@174.334,164.483 173.355,165.989 ; LLC_Transmitter.P$8@174.861,165.01 173.355,165.989 ; 173.355,165.989 LLC_Transmitter.P$8@174.625,164.719 173.355,165.989
VDD: 
pads on no net: 7407_2.10 7407_2.11 7407_2.12 7407_2.13 7407_3.10 7407_3.11 7407_3.12 7407_3.13 7407_4.10 7407_4.11 7407_4.12 7407_4.13 7810.0 "5V to 3.3V.0" "CAN bus 1.5" "CAN bus 1.8" "CAN bus 2.5" "CAN bus 2.8" "Inductive IC(7407).8" "Inductive IC(7407).9" "Inductive IC(7407).10" "Inductive IC(7407).11" "Inductive IC(7407).12" "Inductive IC(7407).13" "RS232 out 1.1" "RS232 out 1.2" "RS232 out 1.4" "RS232 out 1.6" "RS232 out 1.7" "RS232 out 1.8" "RS232 out 1.10" "RS232 out 2.1" "RS232 out 2.2" "RS232 out 2.4" "RS232 out 2.6" "RS232 out 2.7" "RS232 out 2.8" "RS232 out 2.10" DC_motor1.2 DC_motor2.2 DC_MotorDriver1(7407).4 DC_MotorDriver1(7407).6 DC_MotorDriver1(7407).10 DC_MotorDriver1(7407).12 DSwitch2.7 DSwitch3.7 DSwitch.7 LLC_DCMotor1.P$1 LLC_DCMotor1.P$2 LLC_DCMotor1.P$4 LLC_DCMotor1.P$5 LLC_DCMotor1.P$9 LLC_DCMotor1.P$12 LLC_DCMotor2.P$2 LLC_DCMotor2.P$5 LLC_DCMotor2.P$6 LLC_DCMotor2.P$7 LLC_InductiveSensor.P$6 LLC_InductiveSensor.P$7 LLC_RTD.P$1 LLC_RTD.P$2 LLC_RTD.P$11 LLC_RTD.P$12 MAX232_1.11 MAX232_1.12 MAX232_1.13 MAX232_1.14 MAX232_2.11 MAX232_2.12 MAX232_2.13 MAX232_2.14

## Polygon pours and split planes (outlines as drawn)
GND on Bottom Layer "Bottom Layer-No Net" (solid, pour order 6): 157.226,256.794 335.534,256.794 335.788,257.048 335.407,256.667 335.407,56.388 157.861,56.388 157.226,57.023 157.226,256.794
GND on Top Layer "Bottom Layer-No Net" (solid, pour order 8): 157.226,256.794 335.153,256.794 335.407,256.54 335.407,56.642 157.226,56.642 157.226,256.794

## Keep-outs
Keep-Out Layer:
  lines w0.254: 157.226,84.328 157.226,256.794 335.407,256.794 335.407,56.388 157.226,56.388 157.226,89.281

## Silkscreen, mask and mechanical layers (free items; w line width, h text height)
Top Overlay:
  text "<-ground->" at 175.006,243.332 h0.8
  text "+24" at 330.835,238.633 h1
  text "+24" at 330.835,233.68 h1
  text "<-ground->" at 282.448,232.791 h0.8
  text "+24" at 330.835,228.854 h1
  text "+24" at 330.962,223.647 h1
  text "GND" at 158.877,209.042 h1
  text "+24" at 331.216,208.407 h1
  text "+24" at 158.75,206.502 h1
  text "+24" at 330.835,203.454 h1
  text "<-ground->" at 282.575,201.422 h0.8
  text "+24" at 331.089,198.374 h1
  text "GND" at 158.75,193.929 h1
  text "+24" at 330.835,193.167 h1
  text "+24" at 158.877,191.516 h1
  text "+24" at 330.962,177.8 h1
  text "GND" at 158.75,175.768 h1
  text "<-ground->" at 176.657,173.609 h0.8 r270
  text "+5" at 158.75,173.101 h1
  text "+24" at 330.581,172.847 h1
  text "<-ground->" at 282.321,171.577 h0.8
  text "+24" at 330.835,167.767 h1
  text "+24" at 330.581,162.56 h1
  text "<-ground->" at 176.53,152.527 h0.8 r270
  text "GND" at 165.227,151.892 h1
  text "GND" at 331.216,151.892 h1
  text "+10" at 331.216,149.733 h1
  text "+5" at 165.227,149.352 h1
  text "GND" at 330.708,134.493 h1
  text "<-ground->" at 238.125,133.604 h0.8 r270
  text "GND" at 160.909,132.588 h1.52
  text "+10" at 330.708,132.334 h1
  text "+" at 223.139,130.175 h1.52
  text "+" at 259.08,125.73 h1.52
  text "<-ground->" at 196.977,124.714 h0.8
  text "<-ground->" at 268.097,124.206 h0.8
  text "+" at 223.266,122.555 h1.52
  text "+" at 252.095,120.269 h1.52
  text "GND" at 331.089,117.856 h1
  text "+" at 223.139,115.824 h1.52
  text "+10" at 331.089,115.697 h1
  text "+" at 259.334,111.252 h1.52
  text "GND" at 161.036,110.363 h1.52
  text "+" at 218.186,108.204 h1.52
  text "<-ground->" at 196.977,107.696 h0.8
  text "+" at 259.588,104.394 h1.52
  text "GND" at 330.835,100.711 h1
  text "+5" at 330.835,98.552 h1
  text "+" at 254.254,97.282 h1.52
  text "+" at 218.313,97.155 h1.52
  text "<-ground->" at 289.56,90.678 h0.8
  text "GND" at 183.896,90.17 h1.52
  text "+" at 257.556,85.217 h1.52
  text "+" at 236.601,81.28 h1.52
  text "GND" at 330.835,81.153 h1
  text "+5" at 330.835,78.994 h1
  text "+" at 204.089,77.47 h1.52
  text "+" at 287.147,77.47 h1.52
  text "GND" at 184.023,72.771 h1.52
  text "+12" at 248.031,60.325 h1
  text "+24" at 238.125,60.198 h1
  text "GND" at 242.951,60.198 h1
  text "GND" at 252.984,60.198 h1
  text "GND" at 232.41,60.071 h1
  text "+5" at 258.191,59.817 h1

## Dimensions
328.93,130.302 to 328.93,118.364 on Mechanical 1
328.93,147.32 to 328.93,135.382 on Mechanical 1
213.487,150.749 to 266.827,150.749 on Mechanical 1
163.195,204.343 to 163.195,194.31 on Mechanical 1
163.195,176.149 to 172.085,174.879 on Mechanical 1
335.407,256.794 to 335.407,56.388 on Mechanical 1
157.226,84.328 to 335.407,56.388 on Mechanical 1
163.195,209.423 to 163.195,228.473 on Mechanical 1
163.195,176.149 to 163.195,189.23 on Mechanical 1
163.195,152.4 to 163.195,163.449 on Mechanical 1
328.93,101.346 to 328.93,113.284 on Mechanical 1
328.93,93.726 to 328.93,81.788 on Mechanical 1
216.027,211.709 to 157.226,256.794 on Mechanical 1
258.966,67.45 to 335.407,56.388 on Mechanical 1
233.566,67.45 to 157.226,56.388 on Mechanical 1
258.966,67.45 to 335.407,56.388 on Mechanical 1
258.966,67.45 to 273.952,63.386 on Mechanical 1
218.58,63.386 to 233.566,67.45 on Mechanical 1
218.58,63.386 to 157.226,56.388 on Mechanical 1
163.195,144.78 to 163.195,130.81 on Mechanical 1
163.195,108.712 to 163.195,120.65 on Mechanical 1
329.311,252.73 to 335.407,256.794 on Mechanical 1
329.311,252.73 to 335.407,256.794 on Mechanical 1
163.322,252.73 to 157.226,256.794 on Mechanical 1
163.322,252.73 to 157.226,256.794 on Mechanical 1
165.227,64.389 to 157.226,56.388 on Mechanical 1
165.227,64.389 to 157.226,56.388 on Mechanical 1
327.406,64.389 to 335.407,56.388 on Mechanical 1
327.406,64.389 to 335.407,56.388 on Mechanical 1
328.93,241.808 to 335.407,256.794 on Mechanical 1
328.93,224.028 to 328.93,211.582 on Mechanical 1
328.93,193.802 to 328.93,180.848 on Mechanical 1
